VERSION 5.7 ;
  NOWIREEXTENSIONATPIN ON ;
  DIVIDERCHAR "/" ;
  BUSBITCHARS "[]" ;
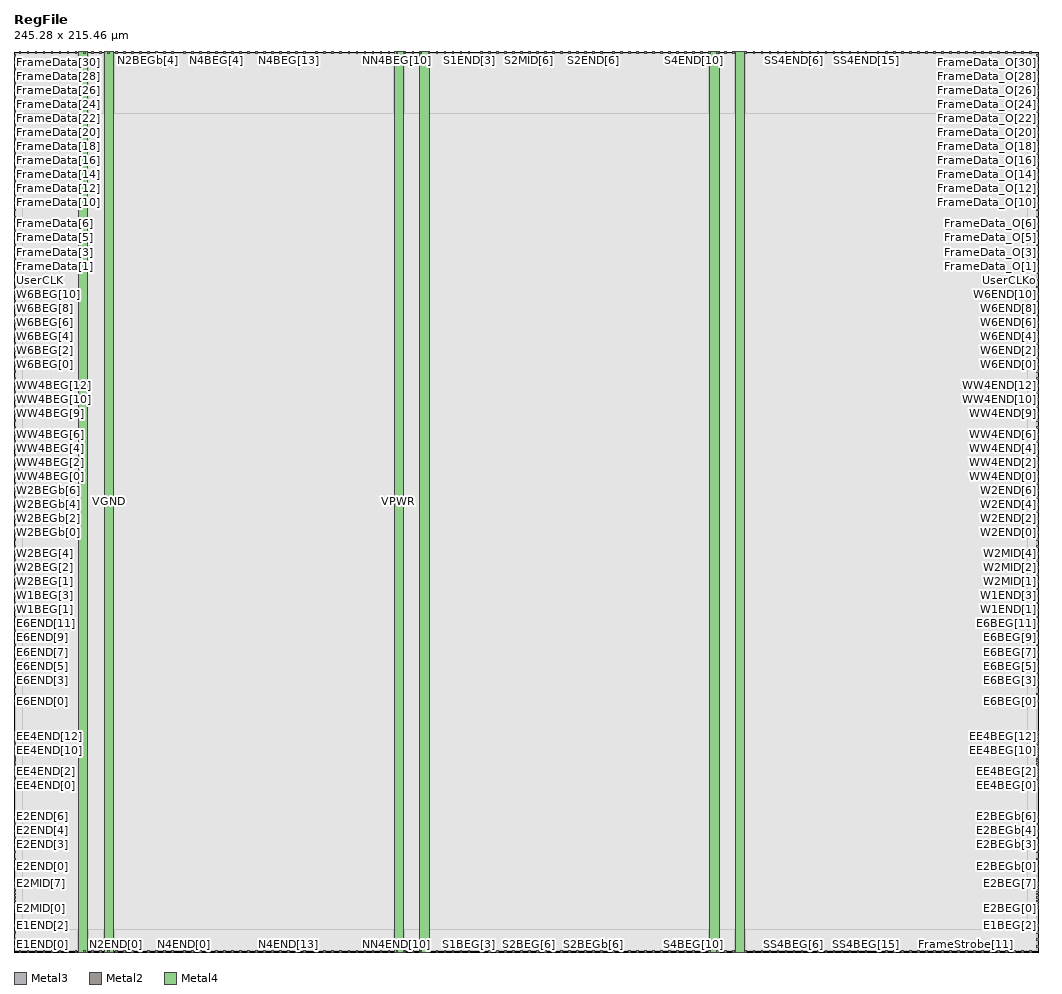
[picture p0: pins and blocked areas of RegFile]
MACRO RegFile
  CLASS BLOCK ;
  FOREIGN RegFile ;
  ORIGIN 0.000 0.000 ;
  SIZE 245.280 BY 215.460 ;
  PIN E1BEG[0]
    DIRECTION OUTPUT ;
    USE SIGNAL ;
    ANTENNADIFFAREA 2.724000 ;
    PORT
      LAYER Metal3 ;
        RECT 244.880 1.060 245.280 1.460 ;
    END
  END E1BEG[0]
  PIN E1BEG[1]
    DIRECTION OUTPUT ;
    USE SIGNAL ;
    ANTENNADIFFAREA 2.724000 ;
    PORT
      LAYER Metal3 ;
        RECT 244.880 2.740 245.280 3.140 ;
    END
  END E1BEG[1]
  PIN E1BEG[2]
    DIRECTION OUTPUT ;
    USE SIGNAL ;
    ANTENNADIFFAREA 2.724000 ;
    PORT
      LAYER Metal3 ;
        RECT 244.880 4.420 245.280 4.820 ;
    END
  END E1BEG[2]
  PIN E1BEG[3]
    DIRECTION OUTPUT ;
    USE SIGNAL ;
    ANTENNADIFFAREA 2.724000 ;
    PORT
      LAYER Metal3 ;
        RECT 244.880 6.100 245.280 6.500 ;
    END
  END E1BEG[3]
  PIN E1END[0]
    DIRECTION INPUT ;
    USE SIGNAL ;
    ANTENNAGATEAREA 1.107600 ;
    PORT
      LAYER Metal3 ;
        RECT 0.000 1.060 0.400 1.460 ;
    END
  END E1END[0]
  PIN E1END[1]
    DIRECTION INPUT ;
    USE SIGNAL ;
    ANTENNAGATEAREA 1.957800 ;
    PORT
      LAYER Metal3 ;
        RECT 0.000 2.740 0.400 3.140 ;
    END
  END E1END[1]
  PIN E1END[2]
    DIRECTION INPUT ;
    USE SIGNAL ;
    ANTENNAGATEAREA 2.319200 ;
    PORT
      LAYER Metal3 ;
        RECT 0.000 4.420 0.400 4.820 ;
    END
  END E1END[2]
  PIN E1END[3]
    DIRECTION INPUT ;
    USE SIGNAL ;
    ANTENNAGATEAREA 2.425800 ;
    PORT
      LAYER Metal3 ;
        RECT 0.000 6.100 0.400 6.500 ;
    END
  END E1END[3]
  PIN E2BEG[0]
    DIRECTION OUTPUT ;
    USE SIGNAL ;
    ANTENNADIFFAREA 2.724000 ;
    PORT
      LAYER Metal3 ;
        RECT 244.880 10.300 245.280 10.700 ;
    END
  END E2BEG[0]
  PIN E2BEG[1]
    DIRECTION OUTPUT ;
    USE SIGNAL ;
    ANTENNADIFFAREA 2.724000 ;
    PORT
      LAYER Metal3 ;
        RECT 244.880 11.140 245.280 11.540 ;
    END
  END E2BEG[1]
  PIN E2BEG[2]
    DIRECTION OUTPUT ;
    USE SIGNAL ;
    ANTENNADIFFAREA 2.724000 ;
    PORT
      LAYER Metal3 ;
        RECT 244.880 11.980 245.280 12.380 ;
    END
  END E2BEG[2]
  PIN E2BEG[3]
    DIRECTION OUTPUT ;
    USE SIGNAL ;
    ANTENNADIFFAREA 2.724000 ;
    PORT
      LAYER Metal3 ;
        RECT 244.880 12.820 245.280 13.220 ;
    END
  END E2BEG[3]
  PIN E2BEG[4]
    DIRECTION OUTPUT ;
    USE SIGNAL ;
    ANTENNADIFFAREA 2.724000 ;
    PORT
      LAYER Metal3 ;
        RECT 244.880 13.660 245.280 14.060 ;
    END
  END E2BEG[4]
  PIN E2BEG[5]
    DIRECTION OUTPUT ;
    USE SIGNAL ;
    ANTENNADIFFAREA 2.724000 ;
    PORT
      LAYER Metal3 ;
        RECT 244.880 14.500 245.280 14.900 ;
    END
  END E2BEG[5]
  PIN E2BEG[6]
    DIRECTION OUTPUT ;
    USE SIGNAL ;
    ANTENNADIFFAREA 2.724000 ;
    PORT
      LAYER Metal3 ;
        RECT 244.880 15.340 245.280 15.740 ;
    END
  END E2BEG[6]
  PIN E2BEG[7]
    DIRECTION OUTPUT ;
    USE SIGNAL ;
    ANTENNADIFFAREA 2.724000 ;
    PORT
      LAYER Metal3 ;
        RECT 244.880 16.180 245.280 16.580 ;
    END
  END E2BEG[7]
  PIN E2BEGb[0]
    DIRECTION OUTPUT ;
    USE SIGNAL ;
    ANTENNADIFFAREA 2.724000 ;
    PORT
      LAYER Metal3 ;
        RECT 244.880 20.380 245.280 20.780 ;
    END
  END E2BEGb[0]
  PIN E2BEGb[1]
    DIRECTION OUTPUT ;
    USE SIGNAL ;
    ANTENNADIFFAREA 2.724000 ;
    PORT
      LAYER Metal3 ;
        RECT 244.880 22.060 245.280 22.460 ;
    END
  END E2BEGb[1]
  PIN E2BEGb[2]
    DIRECTION OUTPUT ;
    USE SIGNAL ;
    ANTENNADIFFAREA 2.724000 ;
    PORT
      LAYER Metal3 ;
        RECT 244.880 23.740 245.280 24.140 ;
    END
  END E2BEGb[2]
  PIN E2BEGb[3]
    DIRECTION OUTPUT ;
    USE SIGNAL ;
    ANTENNADIFFAREA 2.724000 ;
    PORT
      LAYER Metal3 ;
        RECT 244.880 25.420 245.280 25.820 ;
    END
  END E2BEGb[3]
  PIN E2BEGb[4]
    DIRECTION OUTPUT ;
    USE SIGNAL ;
    ANTENNADIFFAREA 2.724000 ;
    PORT
      LAYER Metal3 ;
        RECT 244.880 27.100 245.280 27.500 ;
    END
  END E2BEGb[4]
  PIN E2BEGb[5]
    DIRECTION OUTPUT ;
    USE SIGNAL ;
    ANTENNADIFFAREA 2.724000 ;
    PORT
      LAYER Metal3 ;
        RECT 244.880 28.780 245.280 29.180 ;
    END
  END E2BEGb[5]
  PIN E2BEGb[6]
    DIRECTION OUTPUT ;
    USE SIGNAL ;
    ANTENNADIFFAREA 2.724000 ;
    PORT
      LAYER Metal3 ;
        RECT 244.880 30.460 245.280 30.860 ;
    END
  END E2BEGb[6]
  PIN E2BEGb[7]
    DIRECTION OUTPUT ;
    USE SIGNAL ;
    ANTENNADIFFAREA 2.724000 ;
    PORT
      LAYER Metal3 ;
        RECT 244.880 32.140 245.280 32.540 ;
    END
  END E2BEGb[7]
  PIN E2END[0]
    DIRECTION INPUT ;
    USE SIGNAL ;
    ANTENNAGATEAREA 1.127900 ;
    PORT
      LAYER Metal3 ;
        RECT 0.000 20.380 0.400 20.780 ;
    END
  END E2END[0]
  PIN E2END[1]
    DIRECTION INPUT ;
    USE SIGNAL ;
    ANTENNAGATEAREA 1.029600 ;
    PORT
      LAYER Metal3 ;
        RECT 0.000 22.060 0.400 22.460 ;
    END
  END E2END[1]
  PIN E2END[2]
    DIRECTION INPUT ;
    USE SIGNAL ;
    ANTENNAGATEAREA 1.841600 ;
    PORT
      LAYER Metal3 ;
        RECT 0.000 23.740 0.400 24.140 ;
    END
  END E2END[2]
  PIN E2END[3]
    DIRECTION INPUT ;
    USE SIGNAL ;
    ANTENNAGATEAREA 1.920400 ;
    PORT
      LAYER Metal3 ;
        RECT 0.000 25.420 0.400 25.820 ;
    END
  END E2END[3]
  PIN E2END[4]
    DIRECTION INPUT ;
    USE SIGNAL ;
    ANTENNAGATEAREA 1.092000 ;
    PORT
      LAYER Metal3 ;
        RECT 0.000 27.100 0.400 27.500 ;
    END
  END E2END[4]
  PIN E2END[5]
    DIRECTION INPUT ;
    USE SIGNAL ;
    ANTENNAGATEAREA 1.305200 ;
    PORT
      LAYER Metal3 ;
        RECT 0.000 28.780 0.400 29.180 ;
    END
  END E2END[5]
  PIN E2END[6]
    DIRECTION INPUT ;
    USE SIGNAL ;
    ANTENNAGATEAREA 1.288300 ;
    PORT
      LAYER Metal3 ;
        RECT 0.000 30.460 0.400 30.860 ;
    END
  END E2END[6]
  PIN E2END[7]
    DIRECTION INPUT ;
    USE SIGNAL ;
    ANTENNAGATEAREA 1.120600 ;
    PORT
      LAYER Metal3 ;
        RECT 0.000 32.140 0.400 32.540 ;
    END
  END E2END[7]
  PIN E2MID[0]
    DIRECTION INPUT ;
    USE SIGNAL ;
    ANTENNAGATEAREA 0.635700 ;
    ANTENNADIFFAREA 12.092400 ;
    PORT
      LAYER Metal3 ;
        RECT 0.000 10.300 0.400 10.700 ;
    END
  END E2MID[0]
  PIN E2MID[1]
    DIRECTION INPUT ;
    USE SIGNAL ;
    ANTENNAGATEAREA 1.062100 ;
    PORT
      LAYER Metal3 ;
        RECT 0.000 11.140 0.400 11.540 ;
    END
  END E2MID[1]
  PIN E2MID[2]
    DIRECTION INPUT ;
    USE SIGNAL ;
    ANTENNAGATEAREA 0.820300 ;
    PORT
      LAYER Metal3 ;
        RECT 0.000 11.980 0.400 12.380 ;
    END
  END E2MID[2]
  PIN E2MID[3]
    DIRECTION INPUT ;
    USE SIGNAL ;
    ANTENNAGATEAREA 1.033500 ;
    PORT
      LAYER Metal3 ;
        RECT 0.000 12.820 0.400 13.220 ;
    END
  END E2MID[3]
  PIN E2MID[4]
    DIRECTION INPUT ;
    USE SIGNAL ;
    ANTENNAGATEAREA 0.833300 ;
    PORT
      LAYER Metal3 ;
        RECT 0.000 13.660 0.400 14.060 ;
    END
  END E2MID[4]
  PIN E2MID[5]
    DIRECTION INPUT ;
    USE SIGNAL ;
    ANTENNAGATEAREA 1.046500 ;
    PORT
      LAYER Metal3 ;
        RECT 0.000 14.500 0.400 14.900 ;
    END
  END E2MID[5]
  PIN E2MID[6]
    DIRECTION INPUT ;
    USE SIGNAL ;
    ANTENNAGATEAREA 0.820300 ;
    ANTENNADIFFAREA 8.061600 ;
    PORT
      LAYER Metal3 ;
        RECT 0.000 15.340 0.400 15.740 ;
    END
  END E2MID[6]
  PIN E2MID[7]
    DIRECTION INPUT ;
    USE SIGNAL ;
    ANTENNAGATEAREA 1.046500 ;
    PORT
      LAYER Metal3 ;
        RECT 0.000 16.180 0.400 16.580 ;
    END
  END E2MID[7]
  PIN E6BEG[0]
    DIRECTION OUTPUT ;
    USE SIGNAL ;
    ANTENNADIFFAREA 2.724000 ;
    PORT
      LAYER Metal3 ;
        RECT 244.880 59.860 245.280 60.260 ;
    END
  END E6BEG[0]
  PIN E6BEG[10]
    DIRECTION OUTPUT ;
    USE SIGNAL ;
    ANTENNADIFFAREA 2.724000 ;
    PORT
      LAYER Metal3 ;
        RECT 244.880 76.660 245.280 77.060 ;
    END
  END E6BEG[10]
  PIN E6BEG[11]
    DIRECTION OUTPUT ;
    USE SIGNAL ;
    ANTENNADIFFAREA 2.724000 ;
    PORT
      LAYER Metal3 ;
        RECT 244.880 78.340 245.280 78.740 ;
    END
  END E6BEG[11]
  PIN E6BEG[1]
    DIRECTION OUTPUT ;
    USE SIGNAL ;
    ANTENNADIFFAREA 2.724000 ;
    PORT
      LAYER Metal3 ;
        RECT 244.880 61.540 245.280 61.940 ;
    END
  END E6BEG[1]
  PIN E6BEG[2]
    DIRECTION OUTPUT ;
    USE SIGNAL ;
    ANTENNADIFFAREA 2.724000 ;
    PORT
      LAYER Metal3 ;
        RECT 244.880 63.220 245.280 63.620 ;
    END
  END E6BEG[2]
  PIN E6BEG[3]
    DIRECTION OUTPUT ;
    USE SIGNAL ;
    ANTENNADIFFAREA 2.724000 ;
    PORT
      LAYER Metal3 ;
        RECT 244.880 64.900 245.280 65.300 ;
    END
  END E6BEG[3]
  PIN E6BEG[4]
    DIRECTION OUTPUT ;
    USE SIGNAL ;
    ANTENNADIFFAREA 2.724000 ;
    PORT
      LAYER Metal3 ;
        RECT 244.880 66.580 245.280 66.980 ;
    END
  END E6BEG[4]
  PIN E6BEG[5]
    DIRECTION OUTPUT ;
    USE SIGNAL ;
    ANTENNADIFFAREA 2.724000 ;
    PORT
      LAYER Metal3 ;
        RECT 244.880 68.260 245.280 68.660 ;
    END
  END E6BEG[5]
  PIN E6BEG[6]
    DIRECTION OUTPUT ;
    USE SIGNAL ;
    ANTENNADIFFAREA 2.724000 ;
    PORT
      LAYER Metal3 ;
        RECT 244.880 69.940 245.280 70.340 ;
    END
  END E6BEG[6]
  PIN E6BEG[7]
    DIRECTION OUTPUT ;
    USE SIGNAL ;
    ANTENNADIFFAREA 2.724000 ;
    PORT
      LAYER Metal3 ;
        RECT 244.880 71.620 245.280 72.020 ;
    END
  END E6BEG[7]
  PIN E6BEG[8]
    DIRECTION OUTPUT ;
    USE SIGNAL ;
    ANTENNADIFFAREA 2.724000 ;
    PORT
      LAYER Metal3 ;
        RECT 244.880 73.300 245.280 73.700 ;
    END
  END E6BEG[8]
  PIN E6BEG[9]
    DIRECTION OUTPUT ;
    USE SIGNAL ;
    ANTENNADIFFAREA 2.724000 ;
    PORT
      LAYER Metal3 ;
        RECT 244.880 74.980 245.280 75.380 ;
    END
  END E6BEG[9]
  PIN E6END[0]
    DIRECTION INPUT ;
    USE SIGNAL ;
    ANTENNAGATEAREA 2.633300 ;
    PORT
      LAYER Metal3 ;
        RECT 0.000 59.860 0.400 60.260 ;
    END
  END E6END[0]
  PIN E6END[10]
    DIRECTION INPUT ;
    USE SIGNAL ;
    ANTENNAGATEAREA 0.180700 ;
    PORT
      LAYER Metal3 ;
        RECT 0.000 76.660 0.400 77.060 ;
    END
  END E6END[10]
  PIN E6END[11]
    DIRECTION INPUT ;
    USE SIGNAL ;
    ANTENNAGATEAREA 0.180700 ;
    PORT
      LAYER Metal3 ;
        RECT 0.000 78.340 0.400 78.740 ;
    END
  END E6END[11]
  PIN E6END[1]
    DIRECTION INPUT ;
    USE SIGNAL ;
    ANTENNAGATEAREA 2.641600 ;
    PORT
      LAYER Metal3 ;
        RECT 0.000 61.540 0.400 61.940 ;
    END
  END E6END[1]
  PIN E6END[2]
    DIRECTION INPUT ;
    USE SIGNAL ;
    ANTENNAGATEAREA 0.180700 ;
    PORT
      LAYER Metal3 ;
        RECT 0.000 63.220 0.400 63.620 ;
    END
  END E6END[2]
  PIN E6END[3]
    DIRECTION INPUT ;
    USE SIGNAL ;
    ANTENNAGATEAREA 0.180700 ;
    PORT
      LAYER Metal3 ;
        RECT 0.000 64.900 0.400 65.300 ;
    END
  END E6END[3]
  PIN E6END[4]
    DIRECTION INPUT ;
    USE SIGNAL ;
    ANTENNAGATEAREA 0.180700 ;
    PORT
      LAYER Metal3 ;
        RECT 0.000 66.580 0.400 66.980 ;
    END
  END E6END[4]
  PIN E6END[5]
    DIRECTION INPUT ;
    USE SIGNAL ;
    ANTENNAGATEAREA 0.180700 ;
    PORT
      LAYER Metal3 ;
        RECT 0.000 68.260 0.400 68.660 ;
    END
  END E6END[5]
  PIN E6END[6]
    DIRECTION INPUT ;
    USE SIGNAL ;
    ANTENNAGATEAREA 0.180700 ;
    PORT
      LAYER Metal3 ;
        RECT 0.000 69.940 0.400 70.340 ;
    END
  END E6END[6]
  PIN E6END[7]
    DIRECTION INPUT ;
    USE SIGNAL ;
    ANTENNAGATEAREA 0.180700 ;
    PORT
      LAYER Metal3 ;
        RECT 0.000 71.620 0.400 72.020 ;
    END
  END E6END[7]
  PIN E6END[8]
    DIRECTION INPUT ;
    USE SIGNAL ;
    ANTENNAGATEAREA 0.180700 ;
    PORT
      LAYER Metal3 ;
        RECT 0.000 73.300 0.400 73.700 ;
    END
  END E6END[8]
  PIN E6END[9]
    DIRECTION INPUT ;
    USE SIGNAL ;
    ANTENNAGATEAREA 0.180700 ;
    PORT
      LAYER Metal3 ;
        RECT 0.000 74.980 0.400 75.380 ;
    END
  END E6END[9]
  PIN EE4BEG[0]
    DIRECTION OUTPUT ;
    USE SIGNAL ;
    ANTENNADIFFAREA 2.724000 ;
    PORT
      LAYER Metal3 ;
        RECT 244.880 39.700 245.280 40.100 ;
    END
  END EE4BEG[0]
  PIN EE4BEG[10]
    DIRECTION OUTPUT ;
    USE SIGNAL ;
    ANTENNADIFFAREA 2.724000 ;
    PORT
      LAYER Metal3 ;
        RECT 244.880 48.100 245.280 48.500 ;
    END
  END EE4BEG[10]
  PIN EE4BEG[11]
    DIRECTION OUTPUT ;
    USE SIGNAL ;
    ANTENNADIFFAREA 2.724000 ;
    PORT
      LAYER Metal3 ;
        RECT 244.880 48.940 245.280 49.340 ;
    END
  END EE4BEG[11]
  PIN EE4BEG[12]
    DIRECTION OUTPUT ;
    USE SIGNAL ;
    ANTENNADIFFAREA 2.724000 ;
    PORT
      LAYER Metal3 ;
        RECT 244.880 49.780 245.280 50.180 ;
    END
  END EE4BEG[12]
  PIN EE4BEG[13]
    DIRECTION OUTPUT ;
    USE SIGNAL ;
    ANTENNADIFFAREA 2.724000 ;
    PORT
      LAYER Metal3 ;
        RECT 244.880 50.620 245.280 51.020 ;
    END
  END EE4BEG[13]
  PIN EE4BEG[14]
    DIRECTION OUTPUT ;
    USE SIGNAL ;
    ANTENNADIFFAREA 2.724000 ;
    PORT
      LAYER Metal3 ;
        RECT 244.880 51.460 245.280 51.860 ;
    END
  END EE4BEG[14]
  PIN EE4BEG[15]
    DIRECTION OUTPUT ;
    USE SIGNAL ;
    ANTENNADIFFAREA 2.724000 ;
    PORT
      LAYER Metal3 ;
        RECT 244.880 52.300 245.280 52.700 ;
    END
  END EE4BEG[15]
  PIN EE4BEG[1]
    DIRECTION OUTPUT ;
    USE SIGNAL ;
    ANTENNADIFFAREA 2.724000 ;
    PORT
      LAYER Metal3 ;
        RECT 244.880 40.540 245.280 40.940 ;
    END
  END EE4BEG[1]
  PIN EE4BEG[2]
    DIRECTION OUTPUT ;
    USE SIGNAL ;
    ANTENNADIFFAREA 2.724000 ;
    PORT
      LAYER Metal3 ;
        RECT 244.880 41.380 245.280 41.780 ;
    END
  END EE4BEG[2]
  PIN EE4BEG[3]
    DIRECTION OUTPUT ;
    USE SIGNAL ;
    ANTENNADIFFAREA 2.724000 ;
    PORT
      LAYER Metal3 ;
        RECT 244.880 42.220 245.280 42.620 ;
    END
  END EE4BEG[3]
  PIN EE4BEG[4]
    DIRECTION OUTPUT ;
    USE SIGNAL ;
    ANTENNADIFFAREA 2.724000 ;
    PORT
      LAYER Metal3 ;
        RECT 244.880 43.060 245.280 43.460 ;
    END
  END EE4BEG[4]
  PIN EE4BEG[5]
    DIRECTION OUTPUT ;
    USE SIGNAL ;
    ANTENNADIFFAREA 2.724000 ;
    PORT
      LAYER Metal3 ;
        RECT 244.880 43.900 245.280 44.300 ;
    END
  END EE4BEG[5]
  PIN EE4BEG[6]
    DIRECTION OUTPUT ;
    USE SIGNAL ;
    ANTENNADIFFAREA 2.724000 ;
    PORT
      LAYER Metal3 ;
        RECT 244.880 44.740 245.280 45.140 ;
    END
  END EE4BEG[6]
  PIN EE4BEG[7]
    DIRECTION OUTPUT ;
    USE SIGNAL ;
    ANTENNADIFFAREA 2.724000 ;
    PORT
      LAYER Metal3 ;
        RECT 244.880 45.580 245.280 45.980 ;
    END
  END EE4BEG[7]
  PIN EE4BEG[8]
    DIRECTION OUTPUT ;
    USE SIGNAL ;
    ANTENNADIFFAREA 2.724000 ;
    PORT
      LAYER Metal3 ;
        RECT 244.880 46.420 245.280 46.820 ;
    END
  END EE4BEG[8]
  PIN EE4BEG[9]
    DIRECTION OUTPUT ;
    USE SIGNAL ;
    ANTENNADIFFAREA 2.724000 ;
    PORT
      LAYER Metal3 ;
        RECT 244.880 47.260 245.280 47.660 ;
    END
  END EE4BEG[9]
  PIN EE4END[0]
    DIRECTION INPUT ;
    USE SIGNAL ;
    ANTENNAGATEAREA 0.894400 ;
    PORT
      LAYER Metal3 ;
        RECT 0.000 39.700 0.400 40.100 ;
    END
  END EE4END[0]
  PIN EE4END[10]
    DIRECTION INPUT ;
    USE SIGNAL ;
    ANTENNAGATEAREA 0.180700 ;
    PORT
      LAYER Metal3 ;
        RECT 0.000 48.100 0.400 48.500 ;
    END
  END EE4END[10]
  PIN EE4END[11]
    DIRECTION INPUT ;
    USE SIGNAL ;
    ANTENNAGATEAREA 0.180700 ;
    PORT
      LAYER Metal3 ;
        RECT 0.000 48.940 0.400 49.340 ;
    END
  END EE4END[11]
  PIN EE4END[12]
    DIRECTION INPUT ;
    USE SIGNAL ;
    ANTENNAGATEAREA 0.180700 ;
    PORT
      LAYER Metal3 ;
        RECT 0.000 49.780 0.400 50.180 ;
    END
  END EE4END[12]
  PIN EE4END[13]
    DIRECTION INPUT ;
    USE SIGNAL ;
    ANTENNAGATEAREA 0.180700 ;
    PORT
      LAYER Metal3 ;
        RECT 0.000 50.620 0.400 51.020 ;
    END
  END EE4END[13]
  PIN EE4END[14]
    DIRECTION INPUT ;
    USE SIGNAL ;
    ANTENNAGATEAREA 0.180700 ;
    PORT
      LAYER Metal3 ;
        RECT 0.000 51.460 0.400 51.860 ;
    END
  END EE4END[14]
  PIN EE4END[15]
    DIRECTION INPUT ;
    USE SIGNAL ;
    ANTENNAGATEAREA 0.180700 ;
    PORT
      LAYER Metal3 ;
        RECT 0.000 52.300 0.400 52.700 ;
    END
  END EE4END[15]
  PIN EE4END[1]
    DIRECTION INPUT ;
    USE SIGNAL ;
    ANTENNAGATEAREA 0.878800 ;
    PORT
      LAYER Metal3 ;
        RECT 0.000 40.540 0.400 40.940 ;
    END
  END EE4END[1]
  PIN EE4END[2]
    DIRECTION INPUT ;
    USE SIGNAL ;
    ANTENNAGATEAREA 0.865800 ;
    PORT
      LAYER Metal3 ;
        RECT 0.000 41.380 0.400 41.780 ;
    END
  END EE4END[2]
  PIN EE4END[3]
    DIRECTION INPUT ;
    USE SIGNAL ;
    ANTENNAGATEAREA 0.918600 ;
    PORT
      LAYER Metal3 ;
        RECT 0.000 42.220 0.400 42.620 ;
    END
  END EE4END[3]
  PIN EE4END[4]
    DIRECTION INPUT ;
    USE SIGNAL ;
    ANTENNAGATEAREA 0.180700 ;
    PORT
      LAYER Metal3 ;
        RECT 0.000 43.060 0.400 43.460 ;
    END
  END EE4END[4]
  PIN EE4END[5]
    DIRECTION INPUT ;
    USE SIGNAL ;
    ANTENNAGATEAREA 0.180700 ;
    PORT
      LAYER Metal3 ;
        RECT 0.000 43.900 0.400 44.300 ;
    END
  END EE4END[5]
  PIN EE4END[6]
    DIRECTION INPUT ;
    USE SIGNAL ;
    ANTENNAGATEAREA 0.180700 ;
    PORT
      LAYER Metal3 ;
        RECT 0.000 44.740 0.400 45.140 ;
    END
  END EE4END[6]
  PIN EE4END[7]
    DIRECTION INPUT ;
    USE SIGNAL ;
    ANTENNAGATEAREA 0.180700 ;
    PORT
      LAYER Metal3 ;
        RECT 0.000 45.580 0.400 45.980 ;
    END
  END EE4END[7]
  PIN EE4END[8]
    DIRECTION INPUT ;
    USE SIGNAL ;
    ANTENNAGATEAREA 0.180700 ;
    PORT
      LAYER Metal3 ;
        RECT 0.000 46.420 0.400 46.820 ;
    END
  END EE4END[8]
  PIN EE4END[9]
    DIRECTION INPUT ;
    USE SIGNAL ;
    ANTENNAGATEAREA 0.180700 ;
    PORT
      LAYER Metal3 ;
        RECT 0.000 47.260 0.400 47.660 ;
    END
  END EE4END[9]
  PIN FrameData[0]
    DIRECTION INPUT ;
    USE SIGNAL ;
    ANTENNAGATEAREA 2.349100 ;
    PORT
      LAYER Metal3 ;
        RECT 0.000 162.340 0.400 162.740 ;
    END
  END FrameData[0]
  PIN FrameData[10]
    DIRECTION INPUT ;
    USE SIGNAL ;
    ANTENNAGATEAREA 2.529800 ;
    PORT
      LAYER Metal3 ;
        RECT 0.000 179.140 0.400 179.540 ;
    END
  END FrameData[10]
  PIN FrameData[11]
    DIRECTION INPUT ;
    USE SIGNAL ;
    ANTENNAGATEAREA 2.529800 ;
    PORT
      LAYER Metal3 ;
        RECT 0.000 180.820 0.400 181.220 ;
    END
  END FrameData[11]
  PIN FrameData[12]
    DIRECTION INPUT ;
    USE SIGNAL ;
    ANTENNAGATEAREA 2.529800 ;
    PORT
      LAYER Metal3 ;
        RECT 0.000 182.500 0.400 182.900 ;
    END
  END FrameData[12]
  PIN FrameData[13]
    DIRECTION INPUT ;
    USE SIGNAL ;
    ANTENNAGATEAREA 2.529800 ;
    PORT
      LAYER Metal3 ;
        RECT 0.000 184.180 0.400 184.580 ;
    END
  END FrameData[13]
  PIN FrameData[14]
    DIRECTION INPUT ;
    USE SIGNAL ;
    ANTENNAGATEAREA 2.529800 ;
    PORT
      LAYER Metal3 ;
        RECT 0.000 185.860 0.400 186.260 ;
    END
  END FrameData[14]
  PIN FrameData[15]
    DIRECTION INPUT ;
    USE SIGNAL ;
    ANTENNAGATEAREA 2.529800 ;
    PORT
      LAYER Metal3 ;
        RECT 0.000 187.540 0.400 187.940 ;
    END
  END FrameData[15]
  PIN FrameData[16]
    DIRECTION INPUT ;
    USE SIGNAL ;
    ANTENNAGATEAREA 2.529800 ;
    PORT
      LAYER Metal3 ;
        RECT 0.000 189.220 0.400 189.620 ;
    END
  END FrameData[16]
  PIN FrameData[17]
    DIRECTION INPUT ;
    USE SIGNAL ;
    ANTENNAGATEAREA 2.529800 ;
    PORT
      LAYER Metal3 ;
        RECT 0.000 190.900 0.400 191.300 ;
    END
  END FrameData[17]
  PIN FrameData[18]
    DIRECTION INPUT ;
    USE SIGNAL ;
    ANTENNAGATEAREA 2.529800 ;
    PORT
      LAYER Metal3 ;
        RECT 0.000 192.580 0.400 192.980 ;
    END
  END FrameData[18]
  PIN FrameData[19]
    DIRECTION INPUT ;
    USE SIGNAL ;
    ANTENNAGATEAREA 2.529800 ;
    PORT
      LAYER Metal3 ;
        RECT 0.000 194.260 0.400 194.660 ;
    END
  END FrameData[19]
  PIN FrameData[1]
    DIRECTION INPUT ;
    USE SIGNAL ;
    ANTENNAGATEAREA 2.349100 ;
    PORT
      LAYER Metal3 ;
        RECT 0.000 164.020 0.400 164.420 ;
    END
  END FrameData[1]
  PIN FrameData[20]
    DIRECTION INPUT ;
    USE SIGNAL ;
    ANTENNAGATEAREA 2.529800 ;
    PORT
      LAYER Metal3 ;
        RECT 0.000 195.940 0.400 196.340 ;
    END
  END FrameData[20]
  PIN FrameData[21]
    DIRECTION INPUT ;
    USE SIGNAL ;
    ANTENNAGATEAREA 2.529800 ;
    PORT
      LAYER Metal3 ;
        RECT 0.000 197.620 0.400 198.020 ;
    END
  END FrameData[21]
  PIN FrameData[22]
    DIRECTION INPUT ;
    USE SIGNAL ;
    ANTENNAGATEAREA 2.529800 ;
    PORT
      LAYER Metal3 ;
        RECT 0.000 199.300 0.400 199.700 ;
    END
  END FrameData[22]
  PIN FrameData[23]
    DIRECTION INPUT ;
    USE SIGNAL ;
    ANTENNAGATEAREA 2.529800 ;
    PORT
      LAYER Metal3 ;
        RECT 0.000 200.980 0.400 201.380 ;
    END
  END FrameData[23]
  PIN FrameData[24]
    DIRECTION INPUT ;
    USE SIGNAL ;
    ANTENNAGATEAREA 2.529800 ;
    PORT
      LAYER Metal3 ;
        RECT 0.000 202.660 0.400 203.060 ;
    END
  END FrameData[24]
  PIN FrameData[25]
    DIRECTION INPUT ;
    USE SIGNAL ;
    ANTENNAGATEAREA 2.529800 ;
    PORT
      LAYER Metal3 ;
        RECT 0.000 204.340 0.400 204.740 ;
    END
  END FrameData[25]
  PIN FrameData[26]
    DIRECTION INPUT ;
    USE SIGNAL ;
    ANTENNAGATEAREA 2.529800 ;
    PORT
      LAYER Metal3 ;
        RECT 0.000 206.020 0.400 206.420 ;
    END
  END FrameData[26]
  PIN FrameData[27]
    DIRECTION INPUT ;
    USE SIGNAL ;
    ANTENNAGATEAREA 2.529800 ;
    PORT
      LAYER Metal3 ;
        RECT 0.000 207.700 0.400 208.100 ;
    END
  END FrameData[27]
  PIN FrameData[28]
    DIRECTION INPUT ;
    USE SIGNAL ;
    ANTENNAGATEAREA 2.529800 ;
    PORT
      LAYER Metal3 ;
        RECT 0.000 209.380 0.400 209.780 ;
    END
  END FrameData[28]
  PIN FrameData[29]
    DIRECTION INPUT ;
    USE SIGNAL ;
    ANTENNAGATEAREA 2.529800 ;
    PORT
      LAYER Metal3 ;
        RECT 0.000 211.060 0.400 211.460 ;
    END
  END FrameData[29]
  PIN FrameData[2]
    DIRECTION INPUT ;
    USE SIGNAL ;
    ANTENNAGATEAREA 2.529800 ;
    PORT
      LAYER Metal3 ;
        RECT 0.000 165.700 0.400 166.100 ;
    END
  END FrameData[2]
  PIN FrameData[30]
    DIRECTION INPUT ;
    USE SIGNAL ;
    ANTENNAGATEAREA 2.529800 ;
    ANTENNADIFFAREA 28.215599 ;
    PORT
      LAYER Metal3 ;
        RECT 0.000 212.740 0.400 213.140 ;
    END
  END FrameData[30]
  PIN FrameData[31]
    DIRECTION INPUT ;
    USE SIGNAL ;
    ANTENNAGATEAREA 2.529800 ;
    PORT
      LAYER Metal3 ;
        RECT 0.000 214.420 0.400 214.820 ;
    END
  END FrameData[31]
  PIN FrameData[3]
    DIRECTION INPUT ;
    USE SIGNAL ;
    ANTENNAGATEAREA 2.529800 ;
    ANTENNADIFFAREA 64.492798 ;
    PORT
      LAYER Metal3 ;
        RECT 0.000 167.380 0.400 167.780 ;
    END
  END FrameData[3]
  PIN FrameData[4]
    DIRECTION INPUT ;
    USE SIGNAL ;
    ANTENNAGATEAREA 2.529800 ;
    PORT
      LAYER Metal3 ;
        RECT 0.000 169.060 0.400 169.460 ;
    END
  END FrameData[4]
  PIN FrameData[5]
    DIRECTION INPUT ;
    USE SIGNAL ;
    ANTENNAGATEAREA 2.529800 ;
    PORT
      LAYER Metal3 ;
        RECT 0.000 170.740 0.400 171.140 ;
    END
  END FrameData[5]
  PIN FrameData[6]
    DIRECTION INPUT ;
    USE SIGNAL ;
    ANTENNAGATEAREA 2.529800 ;
    PORT
      LAYER Metal3 ;
        RECT 0.000 172.420 0.400 172.820 ;
    END
  END FrameData[6]
  PIN FrameData[7]
    DIRECTION INPUT ;
    USE SIGNAL ;
    ANTENNAGATEAREA 2.529800 ;
    PORT
      LAYER Metal3 ;
        RECT 0.000 174.100 0.400 174.500 ;
    END
  END FrameData[7]
  PIN FrameData[8]
    DIRECTION INPUT ;
    USE SIGNAL ;
    ANTENNAGATEAREA 2.529800 ;
    PORT
      LAYER Metal3 ;
        RECT 0.000 175.780 0.400 176.180 ;
    END
  END FrameData[8]
  PIN FrameData[9]
    DIRECTION INPUT ;
    USE SIGNAL ;
    ANTENNAGATEAREA 2.529800 ;
    PORT
      LAYER Metal3 ;
        RECT 0.000 177.460 0.400 177.860 ;
    END
  END FrameData[9]
  PIN FrameData_O[0]
    DIRECTION OUTPUT ;
    USE SIGNAL ;
    ANTENNADIFFAREA 2.724000 ;
    PORT
      LAYER Metal3 ;
        RECT 244.880 162.340 245.280 162.740 ;
    END
  END FrameData_O[0]
  PIN FrameData_O[10]
    DIRECTION OUTPUT ;
    USE SIGNAL ;
    ANTENNADIFFAREA 2.724000 ;
    PORT
      LAYER Metal3 ;
        RECT 244.880 179.140 245.280 179.540 ;
    END
  END FrameData_O[10]
  PIN FrameData_O[11]
    DIRECTION OUTPUT ;
    USE SIGNAL ;
    ANTENNADIFFAREA 2.724000 ;
    PORT
      LAYER Metal3 ;
        RECT 244.880 180.820 245.280 181.220 ;
    END
  END FrameData_O[11]
  PIN FrameData_O[12]
    DIRECTION OUTPUT ;
    USE SIGNAL ;
    ANTENNADIFFAREA 2.724000 ;
    PORT
      LAYER Metal3 ;
        RECT 244.880 182.500 245.280 182.900 ;
    END
  END FrameData_O[12]
  PIN FrameData_O[13]
    DIRECTION OUTPUT ;
    USE SIGNAL ;
    ANTENNADIFFAREA 2.724000 ;
    PORT
      LAYER Metal3 ;
        RECT 244.880 184.180 245.280 184.580 ;
    END
  END FrameData_O[13]
  PIN FrameData_O[14]
    DIRECTION OUTPUT ;
    USE SIGNAL ;
    ANTENNADIFFAREA 2.724000 ;
    PORT
      LAYER Metal3 ;
        RECT 244.880 185.860 245.280 186.260 ;
    END
  END FrameData_O[14]
  PIN FrameData_O[15]
    DIRECTION OUTPUT ;
    USE SIGNAL ;
    ANTENNADIFFAREA 2.724000 ;
    PORT
      LAYER Metal3 ;
        RECT 244.880 187.540 245.280 187.940 ;
    END
  END FrameData_O[15]
  PIN FrameData_O[16]
    DIRECTION OUTPUT ;
    USE SIGNAL ;
    ANTENNADIFFAREA 2.724000 ;
    PORT
      LAYER Metal3 ;
        RECT 244.880 189.220 245.280 189.620 ;
    END
  END FrameData_O[16]
  PIN FrameData_O[17]
    DIRECTION OUTPUT ;
    USE SIGNAL ;
    ANTENNADIFFAREA 2.724000 ;
    PORT
      LAYER Metal3 ;
        RECT 244.880 190.900 245.280 191.300 ;
    END
  END FrameData_O[17]
  PIN FrameData_O[18]
    DIRECTION OUTPUT ;
    USE SIGNAL ;
    ANTENNADIFFAREA 2.724000 ;
    PORT
      LAYER Metal3 ;
        RECT 244.880 192.580 245.280 192.980 ;
    END
  END FrameData_O[18]
  PIN FrameData_O[19]
    DIRECTION OUTPUT ;
    USE SIGNAL ;
    ANTENNADIFFAREA 2.724000 ;
    PORT
      LAYER Metal3 ;
        RECT 244.880 194.260 245.280 194.660 ;
    END
  END FrameData_O[19]
  PIN FrameData_O[1]
    DIRECTION OUTPUT ;
    USE SIGNAL ;
    ANTENNADIFFAREA 2.724000 ;
    PORT
      LAYER Metal3 ;
        RECT 244.880 164.020 245.280 164.420 ;
    END
  END FrameData_O[1]
  PIN FrameData_O[20]
    DIRECTION OUTPUT ;
    USE SIGNAL ;
    ANTENNADIFFAREA 2.724000 ;
    PORT
      LAYER Metal3 ;
        RECT 244.880 195.940 245.280 196.340 ;
    END
  END FrameData_O[20]
  PIN FrameData_O[21]
    DIRECTION OUTPUT ;
    USE SIGNAL ;
    ANTENNADIFFAREA 2.724000 ;
    PORT
      LAYER Metal3 ;
        RECT 244.880 197.620 245.280 198.020 ;
    END
  END FrameData_O[21]
  PIN FrameData_O[22]
    DIRECTION OUTPUT ;
    USE SIGNAL ;
    ANTENNADIFFAREA 2.724000 ;
    PORT
      LAYER Metal3 ;
        RECT 244.880 199.300 245.280 199.700 ;
    END
  END FrameData_O[22]
  PIN FrameData_O[23]
    DIRECTION OUTPUT ;
    USE SIGNAL ;
    ANTENNADIFFAREA 2.724000 ;
    PORT
      LAYER Metal3 ;
        RECT 244.880 200.980 245.280 201.380 ;
    END
  END FrameData_O[23]
  PIN FrameData_O[24]
    DIRECTION OUTPUT ;
    USE SIGNAL ;
    ANTENNADIFFAREA 2.724000 ;
    PORT
      LAYER Metal3 ;
        RECT 244.880 202.660 245.280 203.060 ;
    END
  END FrameData_O[24]
  PIN FrameData_O[25]
    DIRECTION OUTPUT ;
    USE SIGNAL ;
    ANTENNADIFFAREA 2.724000 ;
    PORT
      LAYER Metal3 ;
        RECT 244.880 204.340 245.280 204.740 ;
    END
  END FrameData_O[25]
  PIN FrameData_O[26]
    DIRECTION OUTPUT ;
    USE SIGNAL ;
    ANTENNADIFFAREA 2.724000 ;
    PORT
      LAYER Metal3 ;
        RECT 244.880 206.020 245.280 206.420 ;
    END
  END FrameData_O[26]
  PIN FrameData_O[27]
    DIRECTION OUTPUT ;
    USE SIGNAL ;
    ANTENNADIFFAREA 2.724000 ;
    PORT
      LAYER Metal3 ;
        RECT 244.880 207.700 245.280 208.100 ;
    END
  END FrameData_O[27]
  PIN FrameData_O[28]
    DIRECTION OUTPUT ;
    USE SIGNAL ;
    ANTENNADIFFAREA 2.724000 ;
    PORT
      LAYER Metal3 ;
        RECT 244.880 209.380 245.280 209.780 ;
    END
  END FrameData_O[28]
  PIN FrameData_O[29]
    DIRECTION OUTPUT ;
    USE SIGNAL ;
    ANTENNADIFFAREA 2.724000 ;
    PORT
      LAYER Metal3 ;
        RECT 244.880 211.060 245.280 211.460 ;
    END
  END FrameData_O[29]
  PIN FrameData_O[2]
    DIRECTION OUTPUT ;
    USE SIGNAL ;
    ANTENNADIFFAREA 2.724000 ;
    PORT
      LAYER Metal3 ;
        RECT 244.880 165.700 245.280 166.100 ;
    END
  END FrameData_O[2]
  PIN FrameData_O[30]
    DIRECTION OUTPUT ;
    USE SIGNAL ;
    ANTENNADIFFAREA 2.724000 ;
    PORT
      LAYER Metal3 ;
        RECT 244.880 212.740 245.280 213.140 ;
    END
  END FrameData_O[30]
  PIN FrameData_O[31]
    DIRECTION OUTPUT ;
    USE SIGNAL ;
    ANTENNADIFFAREA 2.724000 ;
    PORT
      LAYER Metal3 ;
        RECT 244.880 214.420 245.280 214.820 ;
    END
  END FrameData_O[31]
  PIN FrameData_O[3]
    DIRECTION OUTPUT ;
    USE SIGNAL ;
    ANTENNADIFFAREA 2.724000 ;
    PORT
      LAYER Metal3 ;
        RECT 244.880 167.380 245.280 167.780 ;
    END
  END FrameData_O[3]
  PIN FrameData_O[4]
    DIRECTION OUTPUT ;
    USE SIGNAL ;
    ANTENNADIFFAREA 2.724000 ;
    PORT
      LAYER Metal3 ;
        RECT 244.880 169.060 245.280 169.460 ;
    END
  END FrameData_O[4]
  PIN FrameData_O[5]
    DIRECTION OUTPUT ;
    USE SIGNAL ;
    ANTENNADIFFAREA 2.724000 ;
    PORT
      LAYER Metal3 ;
        RECT 244.880 170.740 245.280 171.140 ;
    END
  END FrameData_O[5]
  PIN FrameData_O[6]
    DIRECTION OUTPUT ;
    USE SIGNAL ;
    ANTENNADIFFAREA 2.724000 ;
    PORT
      LAYER Metal3 ;
        RECT 244.880 172.420 245.280 172.820 ;
    END
  END FrameData_O[6]
  PIN FrameData_O[7]
    DIRECTION OUTPUT ;
    USE SIGNAL ;
    ANTENNADIFFAREA 2.724000 ;
    PORT
      LAYER Metal3 ;
        RECT 244.880 174.100 245.280 174.500 ;
    END
  END FrameData_O[7]
  PIN FrameData_O[8]
    DIRECTION OUTPUT ;
    USE SIGNAL ;
    ANTENNADIFFAREA 2.724000 ;
    PORT
      LAYER Metal3 ;
        RECT 244.880 175.780 245.280 176.180 ;
    END
  END FrameData_O[8]
  PIN FrameData_O[9]
    DIRECTION OUTPUT ;
    USE SIGNAL ;
    ANTENNADIFFAREA 2.724000 ;
    PORT
      LAYER Metal3 ;
        RECT 244.880 177.460 245.280 177.860 ;
    END
  END FrameData_O[9]
  PIN FrameStrobe[0]
    DIRECTION INPUT ;
    USE SIGNAL ;
    ANTENNAGATEAREA 6.753500 ;
    PORT
      LAYER Metal2 ;
        RECT 206.680 0.000 207.080 0.400 ;
    END
  END FrameStrobe[0]
  PIN FrameStrobe[10]
    DIRECTION INPUT ;
    USE SIGNAL ;
    ANTENNAGATEAREA 6.753500 ;
    PORT
      LAYER Metal2 ;
        RECT 225.880 0.000 226.280 0.400 ;
    END
  END FrameStrobe[10]
  PIN FrameStrobe[11]
    DIRECTION INPUT ;
    USE SIGNAL ;
    ANTENNAGATEAREA 6.753500 ;
    PORT
      LAYER Metal2 ;
        RECT 227.800 0.000 228.200 0.400 ;
    END
  END FrameStrobe[11]
  PIN FrameStrobe[12]
    DIRECTION INPUT ;
    USE SIGNAL ;
    ANTENNAGATEAREA 6.342700 ;
    PORT
      LAYER Metal2 ;
        RECT 229.720 0.000 230.120 0.400 ;
    END
  END FrameStrobe[12]
  PIN FrameStrobe[13]
    DIRECTION INPUT ;
    USE SIGNAL ;
    ANTENNAGATEAREA 0.180700 ;
    PORT
      LAYER Metal2 ;
        RECT 231.640 0.000 232.040 0.400 ;
    END
  END FrameStrobe[13]
  PIN FrameStrobe[14]
    DIRECTION INPUT ;
    USE SIGNAL ;
    ANTENNAGATEAREA 0.180700 ;
    PORT
      LAYER Metal2 ;
        RECT 233.560 0.000 233.960 0.400 ;
    END
  END FrameStrobe[14]
  PIN FrameStrobe[15]
    DIRECTION INPUT ;
    USE SIGNAL ;
    ANTENNAGATEAREA 0.180700 ;
    PORT
      LAYER Metal2 ;
        RECT 235.480 0.000 235.880 0.400 ;
    END
  END FrameStrobe[15]
  PIN FrameStrobe[16]
    DIRECTION INPUT ;
    USE SIGNAL ;
    ANTENNAGATEAREA 0.180700 ;
    PORT
      LAYER Metal2 ;
        RECT 237.400 0.000 237.800 0.400 ;
    END
  END FrameStrobe[16]
  PIN FrameStrobe[17]
    DIRECTION INPUT ;
    USE SIGNAL ;
    ANTENNAGATEAREA 0.180700 ;
    PORT
      LAYER Metal2 ;
        RECT 239.320 0.000 239.720 0.400 ;
    END
  END FrameStrobe[17]
  PIN FrameStrobe[18]
    DIRECTION INPUT ;
    USE SIGNAL ;
    ANTENNAGATEAREA 0.180700 ;
    PORT
      LAYER Metal2 ;
        RECT 241.240 0.000 241.640 0.400 ;
    END
  END FrameStrobe[18]
  PIN FrameStrobe[19]
    DIRECTION INPUT ;
    USE SIGNAL ;
    ANTENNAGATEAREA 0.180700 ;
    PORT
      LAYER Metal2 ;
        RECT 243.160 0.000 243.560 0.400 ;
    END
  END FrameStrobe[19]
  PIN FrameStrobe[1]
    DIRECTION INPUT ;
    USE SIGNAL ;
    ANTENNAGATEAREA 6.753500 ;
    PORT
      LAYER Metal2 ;
        RECT 208.600 0.000 209.000 0.400 ;
    END
  END FrameStrobe[1]
  PIN FrameStrobe[2]
    DIRECTION INPUT ;
    USE SIGNAL ;
    ANTENNAGATEAREA 6.753500 ;
    PORT
      LAYER Metal2 ;
        RECT 210.520 0.000 210.920 0.400 ;
    END
  END FrameStrobe[2]
  PIN FrameStrobe[3]
    DIRECTION INPUT ;
    USE SIGNAL ;
    ANTENNAGATEAREA 6.753500 ;
    PORT
      LAYER Metal2 ;
        RECT 212.440 0.000 212.840 0.400 ;
    END
  END FrameStrobe[3]
  PIN FrameStrobe[4]
    DIRECTION INPUT ;
    USE SIGNAL ;
    ANTENNAGATEAREA 6.753500 ;
    PORT
      LAYER Metal2 ;
        RECT 214.360 0.000 214.760 0.400 ;
    END
  END FrameStrobe[4]
  PIN FrameStrobe[5]
    DIRECTION INPUT ;
    USE SIGNAL ;
    ANTENNAGATEAREA 6.753500 ;
    PORT
      LAYER Metal2 ;
        RECT 216.280 0.000 216.680 0.400 ;
    END
  END FrameStrobe[5]
  PIN FrameStrobe[6]
    DIRECTION INPUT ;
    USE SIGNAL ;
    ANTENNAGATEAREA 6.753500 ;
    PORT
      LAYER Metal2 ;
        RECT 218.200 0.000 218.600 0.400 ;
    END
  END FrameStrobe[6]
  PIN FrameStrobe[7]
    DIRECTION INPUT ;
    USE SIGNAL ;
    ANTENNAGATEAREA 6.753500 ;
    PORT
      LAYER Metal2 ;
        RECT 220.120 0.000 220.520 0.400 ;
    END
  END FrameStrobe[7]
  PIN FrameStrobe[8]
    DIRECTION INPUT ;
    USE SIGNAL ;
    ANTENNAGATEAREA 6.753500 ;
    PORT
      LAYER Metal2 ;
        RECT 222.040 0.000 222.440 0.400 ;
    END
  END FrameStrobe[8]
  PIN FrameStrobe[9]
    DIRECTION INPUT ;
    USE SIGNAL ;
    ANTENNAGATEAREA 6.753500 ;
    PORT
      LAYER Metal2 ;
        RECT 223.960 0.000 224.360 0.400 ;
    END
  END FrameStrobe[9]
  PIN FrameStrobe_O[0]
    DIRECTION OUTPUT ;
    USE SIGNAL ;
    ANTENNADIFFAREA 2.724000 ;
    PORT
      LAYER Metal2 ;
        RECT 206.680 215.060 207.080 215.460 ;
    END
  END FrameStrobe_O[0]
  PIN FrameStrobe_O[10]
    DIRECTION OUTPUT ;
    USE SIGNAL ;
    ANTENNADIFFAREA 2.724000 ;
    PORT
      LAYER Metal2 ;
        RECT 225.880 215.060 226.280 215.460 ;
    END
  END FrameStrobe_O[10]
  PIN FrameStrobe_O[11]
    DIRECTION OUTPUT ;
    USE SIGNAL ;
    ANTENNADIFFAREA 2.724000 ;
    PORT
      LAYER Metal2 ;
        RECT 227.800 215.060 228.200 215.460 ;
    END
  END FrameStrobe_O[11]
  PIN FrameStrobe_O[12]
    DIRECTION OUTPUT ;
    USE SIGNAL ;
    ANTENNADIFFAREA 2.724000 ;
    PORT
      LAYER Metal2 ;
        RECT 229.720 215.060 230.120 215.460 ;
    END
  END FrameStrobe_O[12]
  PIN FrameStrobe_O[13]
    DIRECTION OUTPUT ;
    USE SIGNAL ;
    ANTENNADIFFAREA 2.724000 ;
    PORT
      LAYER Metal2 ;
        RECT 231.640 215.060 232.040 215.460 ;
    END
  END FrameStrobe_O[13]
  PIN FrameStrobe_O[14]
    DIRECTION OUTPUT ;
    USE SIGNAL ;
    ANTENNADIFFAREA 2.724000 ;
    PORT
      LAYER Metal2 ;
        RECT 233.560 215.060 233.960 215.460 ;
    END
  END FrameStrobe_O[14]
  PIN FrameStrobe_O[15]
    DIRECTION OUTPUT ;
    USE SIGNAL ;
    ANTENNADIFFAREA 2.724000 ;
    PORT
      LAYER Metal2 ;
        RECT 235.480 215.060 235.880 215.460 ;
    END
  END FrameStrobe_O[15]
  PIN FrameStrobe_O[16]
    DIRECTION OUTPUT ;
    USE SIGNAL ;
    ANTENNADIFFAREA 2.724000 ;
    PORT
      LAYER Metal2 ;
        RECT 237.400 215.060 237.800 215.460 ;
    END
  END FrameStrobe_O[16]
  PIN FrameStrobe_O[17]
    DIRECTION OUTPUT ;
    USE SIGNAL ;
    ANTENNADIFFAREA 2.724000 ;
    PORT
      LAYER Metal2 ;
        RECT 239.320 215.060 239.720 215.460 ;
    END
  END FrameStrobe_O[17]
  PIN FrameStrobe_O[18]
    DIRECTION OUTPUT ;
    USE SIGNAL ;
    ANTENNADIFFAREA 2.724000 ;
    PORT
      LAYER Metal2 ;
        RECT 241.240 215.060 241.640 215.460 ;
    END
  END FrameStrobe_O[18]
  PIN FrameStrobe_O[19]
    DIRECTION OUTPUT ;
    USE SIGNAL ;
    ANTENNADIFFAREA 2.724000 ;
    PORT
      LAYER Metal2 ;
        RECT 243.160 215.060 243.560 215.460 ;
    END
  END FrameStrobe_O[19]
  PIN FrameStrobe_O[1]
    DIRECTION OUTPUT ;
    USE SIGNAL ;
    ANTENNADIFFAREA 2.724000 ;
    PORT
      LAYER Metal2 ;
        RECT 208.600 215.060 209.000 215.460 ;
    END
  END FrameStrobe_O[1]
  PIN FrameStrobe_O[2]
    DIRECTION OUTPUT ;
    USE SIGNAL ;
    ANTENNADIFFAREA 2.724000 ;
    PORT
      LAYER Metal2 ;
        RECT 210.520 215.060 210.920 215.460 ;
    END
  END FrameStrobe_O[2]
  PIN FrameStrobe_O[3]
    DIRECTION OUTPUT ;
    USE SIGNAL ;
    ANTENNADIFFAREA 2.724000 ;
    PORT
      LAYER Metal2 ;
        RECT 212.440 215.060 212.840 215.460 ;
    END
  END FrameStrobe_O[3]
  PIN FrameStrobe_O[4]
    DIRECTION OUTPUT ;
    USE SIGNAL ;
    ANTENNADIFFAREA 2.724000 ;
    PORT
      LAYER Metal2 ;
        RECT 214.360 215.060 214.760 215.460 ;
    END
  END FrameStrobe_O[4]
  PIN FrameStrobe_O[5]
    DIRECTION OUTPUT ;
    USE SIGNAL ;
    ANTENNADIFFAREA 2.724000 ;
    PORT
      LAYER Metal2 ;
        RECT 216.280 215.060 216.680 215.460 ;
    END
  END FrameStrobe_O[5]
  PIN FrameStrobe_O[6]
    DIRECTION OUTPUT ;
    USE SIGNAL ;
    ANTENNADIFFAREA 2.724000 ;
    PORT
      LAYER Metal2 ;
        RECT 218.200 215.060 218.600 215.460 ;
    END
  END FrameStrobe_O[6]
  PIN FrameStrobe_O[7]
    DIRECTION OUTPUT ;
    USE SIGNAL ;
    ANTENNADIFFAREA 2.724000 ;
    PORT
      LAYER Metal2 ;
        RECT 220.120 215.060 220.520 215.460 ;
    END
  END FrameStrobe_O[7]
  PIN FrameStrobe_O[8]
    DIRECTION OUTPUT ;
    USE SIGNAL ;
    ANTENNADIFFAREA 2.724000 ;
    PORT
      LAYER Metal2 ;
        RECT 222.040 215.060 222.440 215.460 ;
    END
  END FrameStrobe_O[8]
  PIN FrameStrobe_O[9]
    DIRECTION OUTPUT ;
    USE SIGNAL ;
    ANTENNADIFFAREA 2.724000 ;
    PORT
      LAYER Metal2 ;
        RECT 223.960 215.060 224.360 215.460 ;
    END
  END FrameStrobe_O[9]
  PIN N1BEG[0]
    DIRECTION OUTPUT ;
    USE SIGNAL ;
    ANTENNADIFFAREA 2.724000 ;
    PORT
      LAYER Metal2 ;
        RECT 1.240 215.060 1.640 215.460 ;
    END
  END N1BEG[0]
  PIN N1BEG[1]
    DIRECTION OUTPUT ;
    USE SIGNAL ;
    ANTENNADIFFAREA 2.724000 ;
    PORT
      LAYER Metal2 ;
        RECT 3.160 215.060 3.560 215.460 ;
    END
  END N1BEG[1]
  PIN N1BEG[2]
    DIRECTION OUTPUT ;
    USE SIGNAL ;
    ANTENNADIFFAREA 2.724000 ;
    PORT
      LAYER Metal2 ;
        RECT 5.080 215.060 5.480 215.460 ;
    END
  END N1BEG[2]
  PIN N1BEG[3]
    DIRECTION OUTPUT ;
    USE SIGNAL ;
    ANTENNADIFFAREA 2.724000 ;
    PORT
      LAYER Metal2 ;
        RECT 7.000 215.060 7.400 215.460 ;
    END
  END N1BEG[3]
  PIN N1END[0]
    DIRECTION INPUT ;
    USE SIGNAL ;
    ANTENNAGATEAREA 2.197800 ;
    PORT
      LAYER Metal2 ;
        RECT 1.240 0.000 1.640 0.400 ;
    END
  END N1END[0]
  PIN N1END[1]
    DIRECTION INPUT ;
    USE SIGNAL ;
    ANTENNAGATEAREA 2.145000 ;
    PORT
      LAYER Metal2 ;
        RECT 3.160 0.000 3.560 0.400 ;
    END
  END N1END[1]
  PIN N1END[2]
    DIRECTION INPUT ;
    USE SIGNAL ;
    ANTENNAGATEAREA 2.236800 ;
    PORT
      LAYER Metal2 ;
        RECT 5.080 0.000 5.480 0.400 ;
    END
  END N1END[2]
  PIN N1END[3]
    DIRECTION INPUT ;
    USE SIGNAL ;
    ANTENNAGATEAREA 2.243800 ;
    PORT
      LAYER Metal2 ;
        RECT 7.000 0.000 7.400 0.400 ;
    END
  END N1END[3]
  PIN N2BEG[0]
    DIRECTION OUTPUT ;
    USE SIGNAL ;
    ANTENNADIFFAREA 2.724000 ;
    PORT
      LAYER Metal2 ;
        RECT 8.920 215.060 9.320 215.460 ;
    END
  END N2BEG[0]
  PIN N2BEG[1]
    DIRECTION OUTPUT ;
    USE SIGNAL ;
    ANTENNADIFFAREA 2.724000 ;
    PORT
      LAYER Metal2 ;
        RECT 10.840 215.060 11.240 215.460 ;
    END
  END N2BEG[1]
  PIN N2BEG[2]
    DIRECTION OUTPUT ;
    USE SIGNAL ;
    ANTENNADIFFAREA 2.724000 ;
    PORT
      LAYER Metal2 ;
        RECT 12.760 215.060 13.160 215.460 ;
    END
  END N2BEG[2]
  PIN N2BEG[3]
    DIRECTION OUTPUT ;
    USE SIGNAL ;
    ANTENNADIFFAREA 2.724000 ;
    PORT
      LAYER Metal2 ;
        RECT 14.680 215.060 15.080 215.460 ;
    END
  END N2BEG[3]
  PIN N2BEG[4]
    DIRECTION OUTPUT ;
    USE SIGNAL ;
    ANTENNADIFFAREA 2.724000 ;
    PORT
      LAYER Metal2 ;
        RECT 16.600 215.060 17.000 215.460 ;
    END
  END N2BEG[4]
  PIN N2BEG[5]
    DIRECTION OUTPUT ;
    USE SIGNAL ;
    ANTENNADIFFAREA 2.724000 ;
    PORT
      LAYER Metal2 ;
        RECT 18.520 215.060 18.920 215.460 ;
    END
  END N2BEG[5]
  PIN N2BEG[6]
    DIRECTION OUTPUT ;
    USE SIGNAL ;
    ANTENNADIFFAREA 2.724000 ;
    PORT
      LAYER Metal2 ;
        RECT 20.440 215.060 20.840 215.460 ;
    END
  END N2BEG[6]
  PIN N2BEG[7]
    DIRECTION OUTPUT ;
    USE SIGNAL ;
    ANTENNADIFFAREA 2.724000 ;
    PORT
      LAYER Metal2 ;
        RECT 22.360 215.060 22.760 215.460 ;
    END
  END N2BEG[7]
  PIN N2BEGb[0]
    DIRECTION OUTPUT ;
    USE SIGNAL ;
    ANTENNADIFFAREA 2.724000 ;
    PORT
      LAYER Metal2 ;
        RECT 24.280 215.060 24.680 215.460 ;
    END
  END N2BEGb[0]
  PIN N2BEGb[1]
    DIRECTION OUTPUT ;
    USE SIGNAL ;
    ANTENNADIFFAREA 2.724000 ;
    PORT
      LAYER Metal2 ;
        RECT 26.200 215.060 26.600 215.460 ;
    END
  END N2BEGb[1]
  PIN N2BEGb[2]
    DIRECTION OUTPUT ;
    USE SIGNAL ;
    ANTENNADIFFAREA 2.724000 ;
    PORT
      LAYER Metal2 ;
        RECT 28.120 215.060 28.520 215.460 ;
    END
  END N2BEGb[2]
  PIN N2BEGb[3]
    DIRECTION OUTPUT ;
    USE SIGNAL ;
    ANTENNADIFFAREA 2.724000 ;
    PORT
      LAYER Metal2 ;
        RECT 30.040 215.060 30.440 215.460 ;
    END
  END N2BEGb[3]
  PIN N2BEGb[4]
    DIRECTION OUTPUT ;
    USE SIGNAL ;
    ANTENNADIFFAREA 2.724000 ;
    PORT
      LAYER Metal2 ;
        RECT 31.960 215.060 32.360 215.460 ;
    END
  END N2BEGb[4]
  PIN N2BEGb[5]
    DIRECTION OUTPUT ;
    USE SIGNAL ;
    ANTENNADIFFAREA 2.724000 ;
    PORT
      LAYER Metal2 ;
        RECT 33.880 215.060 34.280 215.460 ;
    END
  END N2BEGb[5]
  PIN N2BEGb[6]
    DIRECTION OUTPUT ;
    USE SIGNAL ;
    ANTENNADIFFAREA 2.724000 ;
    PORT
      LAYER Metal2 ;
        RECT 35.800 215.060 36.200 215.460 ;
    END
  END N2BEGb[6]
  PIN N2BEGb[7]
    DIRECTION OUTPUT ;
    USE SIGNAL ;
    ANTENNADIFFAREA 2.724000 ;
    PORT
      LAYER Metal2 ;
        RECT 37.720 215.060 38.120 215.460 ;
    END
  END N2BEGb[7]
  PIN N2END[0]
    DIRECTION INPUT ;
    USE SIGNAL ;
    ANTENNAGATEAREA 1.771400 ;
    PORT
      LAYER Metal2 ;
        RECT 24.280 0.000 24.680 0.400 ;
    END
  END N2END[0]
  PIN N2END[1]
    DIRECTION INPUT ;
    USE SIGNAL ;
    ANTENNAGATEAREA 1.534000 ;
    PORT
      LAYER Metal2 ;
        RECT 26.200 0.000 26.600 0.400 ;
    END
  END N2END[1]
  PIN N2END[2]
    DIRECTION INPUT ;
    USE SIGNAL ;
    ANTENNAGATEAREA 1.505400 ;
    PORT
      LAYER Metal2 ;
        RECT 28.120 0.000 28.520 0.400 ;
    END
  END N2END[2]
  PIN N2END[3]
    DIRECTION INPUT ;
    USE SIGNAL ;
    ANTENNAGATEAREA 1.705600 ;
    PORT
      LAYER Metal2 ;
        RECT 30.040 0.000 30.440 0.400 ;
    END
  END N2END[3]
  PIN N2END[4]
    DIRECTION INPUT ;
    USE SIGNAL ;
    ANTENNAGATEAREA 1.292200 ;
    PORT
      LAYER Metal2 ;
        RECT 31.960 0.000 32.360 0.400 ;
    END
  END N2END[4]
  PIN N2END[5]
    DIRECTION INPUT ;
    USE SIGNAL ;
    ANTENNAGATEAREA 1.079000 ;
    PORT
      LAYER Metal2 ;
        RECT 33.880 0.000 34.280 0.400 ;
    END
  END N2END[5]
  PIN N2END[6]
    DIRECTION INPUT ;
    USE SIGNAL ;
    ANTENNAGATEAREA 1.092000 ;
    PORT
      LAYER Metal2 ;
        RECT 35.800 0.000 36.200 0.400 ;
    END
  END N2END[6]
  PIN N2END[7]
    DIRECTION INPUT ;
    USE SIGNAL ;
    ANTENNAGATEAREA 1.362400 ;
    PORT
      LAYER Metal2 ;
        RECT 37.720 0.000 38.120 0.400 ;
    END
  END N2END[7]
  PIN N2MID[0]
    DIRECTION INPUT ;
    USE SIGNAL ;
    ANTENNAGATEAREA 0.886100 ;
    ANTENNADIFFAREA 8.061600 ;
    PORT
      LAYER Metal2 ;
        RECT 8.920 0.000 9.320 0.400 ;
    END
  END N2MID[0]
  PIN N2MID[1]
    DIRECTION INPUT ;
    USE SIGNAL ;
    ANTENNAGATEAREA 1.062100 ;
    PORT
      LAYER Metal2 ;
        RECT 10.840 0.000 11.240 0.400 ;
    END
  END N2MID[1]
  PIN N2MID[2]
    DIRECTION INPUT ;
    USE SIGNAL ;
    ANTENNAGATEAREA 0.848900 ;
    ANTENNADIFFAREA 32.246399 ;
    PORT
      LAYER Metal2 ;
        RECT 12.760 0.000 13.160 0.400 ;
    END
  END N2MID[2]
  PIN N2MID[3]
    DIRECTION INPUT ;
    USE SIGNAL ;
    ANTENNAGATEAREA 1.033500 ;
    PORT
      LAYER Metal2 ;
        RECT 14.680 0.000 15.080 0.400 ;
    END
  END N2MID[3]
  PIN N2MID[4]
    DIRECTION INPUT ;
    USE SIGNAL ;
    ANTENNAGATEAREA 0.833300 ;
    ANTENNADIFFAREA 16.123199 ;
    PORT
      LAYER Metal2 ;
        RECT 16.600 0.000 17.000 0.400 ;
    END
  END N2MID[4]
  PIN N2MID[5]
    DIRECTION INPUT ;
    USE SIGNAL ;
    ANTENNAGATEAREA 1.046500 ;
    PORT
      LAYER Metal2 ;
        RECT 18.520 0.000 18.920 0.400 ;
    END
  END N2MID[5]
  PIN N2MID[6]
    DIRECTION INPUT ;
    USE SIGNAL ;
    ANTENNAGATEAREA 0.820300 ;
    PORT
      LAYER Metal2 ;
        RECT 20.440 0.000 20.840 0.400 ;
    END
  END N2MID[6]
  PIN N2MID[7]
    DIRECTION INPUT ;
    USE SIGNAL ;
    ANTENNAGATEAREA 1.046500 ;
    PORT
      LAYER Metal2 ;
        RECT 22.360 0.000 22.760 0.400 ;
    END
  END N2MID[7]
  PIN N4BEG[0]
    DIRECTION OUTPUT ;
    USE SIGNAL ;
    ANTENNADIFFAREA 2.724000 ;
    PORT
      LAYER Metal2 ;
        RECT 40.600 215.060 41.000 215.460 ;
    END
  END N4BEG[0]
  PIN N4BEG[10]
    DIRECTION OUTPUT ;
    USE SIGNAL ;
    ANTENNADIFFAREA 2.724000 ;
    PORT
      LAYER Metal2 ;
        RECT 59.800 215.060 60.200 215.460 ;
    END
  END N4BEG[10]
  PIN N4BEG[11]
    DIRECTION OUTPUT ;
    USE SIGNAL ;
    ANTENNADIFFAREA 2.724000 ;
    PORT
      LAYER Metal2 ;
        RECT 61.720 215.060 62.120 215.460 ;
    END
  END N4BEG[11]
  PIN N4BEG[12]
    DIRECTION OUTPUT ;
    USE SIGNAL ;
    ANTENNADIFFAREA 2.724000 ;
    PORT
      LAYER Metal2 ;
        RECT 63.640 215.060 64.040 215.460 ;
    END
  END N4BEG[12]
  PIN N4BEG[13]
    DIRECTION OUTPUT ;
    USE SIGNAL ;
    ANTENNADIFFAREA 2.724000 ;
    PORT
      LAYER Metal2 ;
        RECT 65.560 215.060 65.960 215.460 ;
    END
  END N4BEG[13]
  PIN N4BEG[14]
    DIRECTION OUTPUT ;
    USE SIGNAL ;
    ANTENNADIFFAREA 2.724000 ;
    PORT
      LAYER Metal2 ;
        RECT 67.480 215.060 67.880 215.460 ;
    END
  END N4BEG[14]
  PIN N4BEG[15]
    DIRECTION OUTPUT ;
    USE SIGNAL ;
    ANTENNADIFFAREA 2.724000 ;
    PORT
      LAYER Metal2 ;
        RECT 69.400 215.060 69.800 215.460 ;
    END
  END N4BEG[15]
  PIN N4BEG[1]
    DIRECTION OUTPUT ;
    USE SIGNAL ;
    ANTENNADIFFAREA 2.724000 ;
    PORT
      LAYER Metal2 ;
        RECT 42.520 215.060 42.920 215.460 ;
    END
  END N4BEG[1]
  PIN N4BEG[2]
    DIRECTION OUTPUT ;
    USE SIGNAL ;
    ANTENNADIFFAREA 2.724000 ;
    PORT
      LAYER Metal2 ;
        RECT 44.440 215.060 44.840 215.460 ;
    END
  END N4BEG[2]
  PIN N4BEG[3]
    DIRECTION OUTPUT ;
    USE SIGNAL ;
    ANTENNADIFFAREA 2.724000 ;
    PORT
      LAYER Metal2 ;
        RECT 46.360 215.060 46.760 215.460 ;
    END
  END N4BEG[3]
  PIN N4BEG[4]
    DIRECTION OUTPUT ;
    USE SIGNAL ;
    ANTENNADIFFAREA 2.724000 ;
    PORT
      LAYER Metal2 ;
        RECT 48.280 215.060 48.680 215.460 ;
    END
  END N4BEG[4]
  PIN N4BEG[5]
    DIRECTION OUTPUT ;
    USE SIGNAL ;
    ANTENNADIFFAREA 2.724000 ;
    PORT
      LAYER Metal2 ;
        RECT 50.200 215.060 50.600 215.460 ;
    END
  END N4BEG[5]
  PIN N4BEG[6]
    DIRECTION OUTPUT ;
    USE SIGNAL ;
    ANTENNADIFFAREA 2.724000 ;
    PORT
      LAYER Metal2 ;
        RECT 52.120 215.060 52.520 215.460 ;
    END
  END N4BEG[6]
  PIN N4BEG[7]
    DIRECTION OUTPUT ;
    USE SIGNAL ;
    ANTENNADIFFAREA 2.724000 ;
    PORT
      LAYER Metal2 ;
        RECT 54.040 215.060 54.440 215.460 ;
    END
  END N4BEG[7]
  PIN N4BEG[8]
    DIRECTION OUTPUT ;
    USE SIGNAL ;
    ANTENNADIFFAREA 2.724000 ;
    PORT
      LAYER Metal2 ;
        RECT 55.960 215.060 56.360 215.460 ;
    END
  END N4BEG[8]
  PIN N4BEG[9]
    DIRECTION OUTPUT ;
    USE SIGNAL ;
    ANTENNADIFFAREA 2.724000 ;
    PORT
      LAYER Metal2 ;
        RECT 57.880 215.060 58.280 215.460 ;
    END
  END N4BEG[9]
  PIN N4END[0]
    DIRECTION INPUT ;
    USE SIGNAL ;
    ANTENNAGATEAREA 1.059500 ;
    PORT
      LAYER Metal2 ;
        RECT 40.600 0.000 41.000 0.400 ;
    END
  END N4END[0]
  PIN N4END[10]
    DIRECTION INPUT ;
    USE SIGNAL ;
    ANTENNAGATEAREA 0.180700 ;
    PORT
      LAYER Metal2 ;
        RECT 59.800 0.000 60.200 0.400 ;
    END
  END N4END[10]
  PIN N4END[11]
    DIRECTION INPUT ;
    USE SIGNAL ;
    ANTENNAGATEAREA 0.180700 ;
    PORT
      LAYER Metal2 ;
        RECT 61.720 0.000 62.120 0.400 ;
    END
  END N4END[11]
  PIN N4END[12]
    DIRECTION INPUT ;
    USE SIGNAL ;
    ANTENNAGATEAREA 0.180700 ;
    PORT
      LAYER Metal2 ;
        RECT 63.640 0.000 64.040 0.400 ;
    END
  END N4END[12]
  PIN N4END[13]
    DIRECTION INPUT ;
    USE SIGNAL ;
    ANTENNAGATEAREA 0.180700 ;
    PORT
      LAYER Metal2 ;
        RECT 65.560 0.000 65.960 0.400 ;
    END
  END N4END[13]
  PIN N4END[14]
    DIRECTION INPUT ;
    USE SIGNAL ;
    ANTENNAGATEAREA 0.180700 ;
    PORT
      LAYER Metal2 ;
        RECT 67.480 0.000 67.880 0.400 ;
    END
  END N4END[14]
  PIN N4END[15]
    DIRECTION INPUT ;
    USE SIGNAL ;
    ANTENNAGATEAREA 0.180700 ;
    PORT
      LAYER Metal2 ;
        RECT 69.400 0.000 69.800 0.400 ;
    END
  END N4END[15]
  PIN N4END[1]
    DIRECTION INPUT ;
    USE SIGNAL ;
    ANTENNAGATEAREA 0.668200 ;
    PORT
      LAYER Metal2 ;
        RECT 42.520 0.000 42.920 0.400 ;
    END
  END N4END[1]
  PIN N4END[2]
    DIRECTION INPUT ;
    USE SIGNAL ;
    ANTENNAGATEAREA 1.092000 ;
    PORT
      LAYER Metal2 ;
        RECT 44.440 0.000 44.840 0.400 ;
    END
  END N4END[2]
  PIN N4END[3]
    DIRECTION INPUT ;
    USE SIGNAL ;
    ANTENNAGATEAREA 0.968500 ;
    PORT
      LAYER Metal2 ;
        RECT 46.360 0.000 46.760 0.400 ;
    END
  END N4END[3]
  PIN N4END[4]
    DIRECTION INPUT ;
    USE SIGNAL ;
    ANTENNAGATEAREA 0.180700 ;
    PORT
      LAYER Metal2 ;
        RECT 48.280 0.000 48.680 0.400 ;
    END
  END N4END[4]
  PIN N4END[5]
    DIRECTION INPUT ;
    USE SIGNAL ;
    ANTENNAGATEAREA 0.180700 ;
    PORT
      LAYER Metal2 ;
        RECT 50.200 0.000 50.600 0.400 ;
    END
  END N4END[5]
  PIN N4END[6]
    DIRECTION INPUT ;
    USE SIGNAL ;
    ANTENNAGATEAREA 0.180700 ;
    PORT
      LAYER Metal2 ;
        RECT 52.120 0.000 52.520 0.400 ;
    END
  END N4END[6]
  PIN N4END[7]
    DIRECTION INPUT ;
    USE SIGNAL ;
    ANTENNAGATEAREA 0.180700 ;
    PORT
      LAYER Metal2 ;
        RECT 54.040 0.000 54.440 0.400 ;
    END
  END N4END[7]
  PIN N4END[8]
    DIRECTION INPUT ;
    USE SIGNAL ;
    ANTENNAGATEAREA 0.180700 ;
    PORT
      LAYER Metal2 ;
        RECT 55.960 0.000 56.360 0.400 ;
    END
  END N4END[8]
  PIN N4END[9]
    DIRECTION INPUT ;
    USE SIGNAL ;
    ANTENNAGATEAREA 0.180700 ;
    PORT
      LAYER Metal2 ;
        RECT 57.880 0.000 58.280 0.400 ;
    END
  END N4END[9]
  PIN NN4BEG[0]
    DIRECTION OUTPUT ;
    USE SIGNAL ;
    ANTENNADIFFAREA 2.724000 ;
    PORT
      LAYER Metal2 ;
        RECT 72.280 215.060 72.680 215.460 ;
    END
  END NN4BEG[0]
  PIN NN4BEG[10]
    DIRECTION OUTPUT ;
    USE SIGNAL ;
    ANTENNADIFFAREA 2.724000 ;
    PORT
      LAYER Metal2 ;
        RECT 91.480 215.060 91.880 215.460 ;
    END
  END NN4BEG[10]
  PIN NN4BEG[11]
    DIRECTION OUTPUT ;
    USE SIGNAL ;
    ANTENNADIFFAREA 2.724000 ;
    PORT
      LAYER Metal2 ;
        RECT 93.400 215.060 93.800 215.460 ;
    END
  END NN4BEG[11]
  PIN NN4BEG[12]
    DIRECTION OUTPUT ;
    USE SIGNAL ;
    ANTENNADIFFAREA 2.724000 ;
    PORT
      LAYER Metal2 ;
        RECT 95.320 215.060 95.720 215.460 ;
    END
  END NN4BEG[12]
  PIN NN4BEG[13]
    DIRECTION OUTPUT ;
    USE SIGNAL ;
    ANTENNADIFFAREA 2.724000 ;
    PORT
      LAYER Metal2 ;
        RECT 97.240 215.060 97.640 215.460 ;
    END
  END NN4BEG[13]
  PIN NN4BEG[14]
    DIRECTION OUTPUT ;
    USE SIGNAL ;
    ANTENNADIFFAREA 2.724000 ;
    PORT
      LAYER Metal2 ;
        RECT 99.160 215.060 99.560 215.460 ;
    END
  END NN4BEG[14]
  PIN NN4BEG[15]
    DIRECTION OUTPUT ;
    USE SIGNAL ;
    ANTENNADIFFAREA 2.724000 ;
    PORT
      LAYER Metal2 ;
        RECT 101.080 215.060 101.480 215.460 ;
    END
  END NN4BEG[15]
  PIN NN4BEG[1]
    DIRECTION OUTPUT ;
    USE SIGNAL ;
    ANTENNADIFFAREA 2.724000 ;
    PORT
      LAYER Metal2 ;
        RECT 74.200 215.060 74.600 215.460 ;
    END
  END NN4BEG[1]
  PIN NN4BEG[2]
    DIRECTION OUTPUT ;
    USE SIGNAL ;
    ANTENNADIFFAREA 2.724000 ;
    PORT
      LAYER Metal2 ;
        RECT 76.120 215.060 76.520 215.460 ;
    END
  END NN4BEG[2]
  PIN NN4BEG[3]
    DIRECTION OUTPUT ;
    USE SIGNAL ;
    ANTENNADIFFAREA 2.724000 ;
    PORT
      LAYER Metal2 ;
        RECT 78.040 215.060 78.440 215.460 ;
    END
  END NN4BEG[3]
  PIN NN4BEG[4]
    DIRECTION OUTPUT ;
    USE SIGNAL ;
    ANTENNADIFFAREA 2.724000 ;
    PORT
      LAYER Metal2 ;
        RECT 79.960 215.060 80.360 215.460 ;
    END
  END NN4BEG[4]
  PIN NN4BEG[5]
    DIRECTION OUTPUT ;
    USE SIGNAL ;
    ANTENNADIFFAREA 2.724000 ;
    PORT
      LAYER Metal2 ;
        RECT 81.880 215.060 82.280 215.460 ;
    END
  END NN4BEG[5]
  PIN NN4BEG[6]
    DIRECTION OUTPUT ;
    USE SIGNAL ;
    ANTENNADIFFAREA 2.724000 ;
    PORT
      LAYER Metal2 ;
        RECT 83.800 215.060 84.200 215.460 ;
    END
  END NN4BEG[6]
  PIN NN4BEG[7]
    DIRECTION OUTPUT ;
    USE SIGNAL ;
    ANTENNADIFFAREA 2.724000 ;
    PORT
      LAYER Metal2 ;
        RECT 85.720 215.060 86.120 215.460 ;
    END
  END NN4BEG[7]
  PIN NN4BEG[8]
    DIRECTION OUTPUT ;
    USE SIGNAL ;
    ANTENNADIFFAREA 2.724000 ;
    PORT
      LAYER Metal2 ;
        RECT 87.640 215.060 88.040 215.460 ;
    END
  END NN4BEG[8]
  PIN NN4BEG[9]
    DIRECTION OUTPUT ;
    USE SIGNAL ;
    ANTENNADIFFAREA 2.724000 ;
    PORT
      LAYER Metal2 ;
        RECT 89.560 215.060 89.960 215.460 ;
    END
  END NN4BEG[9]
  PIN NN4END[0]
    DIRECTION INPUT ;
    USE SIGNAL ;
    ANTENNAGATEAREA 1.107600 ;
    PORT
      LAYER Metal2 ;
        RECT 72.280 0.000 72.680 0.400 ;
    END
  END NN4END[0]
  PIN NN4END[10]
    DIRECTION INPUT ;
    USE SIGNAL ;
    ANTENNAGATEAREA 0.180700 ;
    PORT
      LAYER Metal2 ;
        RECT 91.480 0.000 91.880 0.400 ;
    END
  END NN4END[10]
  PIN NN4END[11]
    DIRECTION INPUT ;
    USE SIGNAL ;
    ANTENNAGATEAREA 0.180700 ;
    PORT
      LAYER Metal2 ;
        RECT 93.400 0.000 93.800 0.400 ;
    END
  END NN4END[11]
  PIN NN4END[12]
    DIRECTION INPUT ;
    USE SIGNAL ;
    ANTENNAGATEAREA 0.180700 ;
    PORT
      LAYER Metal2 ;
        RECT 95.320 0.000 95.720 0.400 ;
    END
  END NN4END[12]
  PIN NN4END[13]
    DIRECTION INPUT ;
    USE SIGNAL ;
    ANTENNAGATEAREA 0.180700 ;
    PORT
      LAYER Metal2 ;
        RECT 97.240 0.000 97.640 0.400 ;
    END
  END NN4END[13]
  PIN NN4END[14]
    DIRECTION INPUT ;
    USE SIGNAL ;
    ANTENNAGATEAREA 0.180700 ;
    PORT
      LAYER Metal2 ;
        RECT 99.160 0.000 99.560 0.400 ;
    END
  END NN4END[14]
  PIN NN4END[15]
    DIRECTION INPUT ;
    USE SIGNAL ;
    ANTENNAGATEAREA 0.180700 ;
    PORT
      LAYER Metal2 ;
        RECT 101.080 0.000 101.480 0.400 ;
    END
  END NN4END[15]
  PIN NN4END[1]
    DIRECTION INPUT ;
    USE SIGNAL ;
    ANTENNAGATEAREA 1.059500 ;
    PORT
      LAYER Metal2 ;
        RECT 74.200 0.000 74.600 0.400 ;
    END
  END NN4END[1]
  PIN NN4END[2]
    DIRECTION INPUT ;
    USE SIGNAL ;
    ANTENNAGATEAREA 1.120600 ;
    PORT
      LAYER Metal2 ;
        RECT 76.120 0.000 76.520 0.400 ;
    END
  END NN4END[2]
  PIN NN4END[3]
    DIRECTION INPUT ;
    USE SIGNAL ;
    ANTENNAGATEAREA 1.066000 ;
    PORT
      LAYER Metal2 ;
        RECT 78.040 0.000 78.440 0.400 ;
    END
  END NN4END[3]
  PIN NN4END[4]
    DIRECTION INPUT ;
    USE SIGNAL ;
    ANTENNAGATEAREA 0.180700 ;
    PORT
      LAYER Metal2 ;
        RECT 79.960 0.000 80.360 0.400 ;
    END
  END NN4END[4]
  PIN NN4END[5]
    DIRECTION INPUT ;
    USE SIGNAL ;
    ANTENNAGATEAREA 0.180700 ;
    PORT
      LAYER Metal2 ;
        RECT 81.880 0.000 82.280 0.400 ;
    END
  END NN4END[5]
  PIN NN4END[6]
    DIRECTION INPUT ;
    USE SIGNAL ;
    ANTENNAGATEAREA 0.180700 ;
    PORT
      LAYER Metal2 ;
        RECT 83.800 0.000 84.200 0.400 ;
    END
  END NN4END[6]
  PIN NN4END[7]
    DIRECTION INPUT ;
    USE SIGNAL ;
    ANTENNAGATEAREA 0.180700 ;
    PORT
      LAYER Metal2 ;
        RECT 85.720 0.000 86.120 0.400 ;
    END
  END NN4END[7]
  PIN NN4END[8]
    DIRECTION INPUT ;
    USE SIGNAL ;
    ANTENNAGATEAREA 0.180700 ;
    PORT
      LAYER Metal2 ;
        RECT 87.640 0.000 88.040 0.400 ;
    END
  END NN4END[8]
  PIN NN4END[9]
    DIRECTION INPUT ;
    USE SIGNAL ;
    ANTENNAGATEAREA 0.180700 ;
    PORT
      LAYER Metal2 ;
        RECT 89.560 0.000 89.960 0.400 ;
    END
  END NN4END[9]
  PIN S1BEG[0]
    DIRECTION OUTPUT ;
    USE SIGNAL ;
    ANTENNADIFFAREA 2.724000 ;
    PORT
      LAYER Metal2 ;
        RECT 103.000 0.000 103.400 0.400 ;
    END
  END S1BEG[0]
  PIN S1BEG[1]
    DIRECTION OUTPUT ;
    USE SIGNAL ;
    ANTENNADIFFAREA 2.724000 ;
    PORT
      LAYER Metal2 ;
        RECT 104.920 0.000 105.320 0.400 ;
    END
  END S1BEG[1]
  PIN S1BEG[2]
    DIRECTION OUTPUT ;
    USE SIGNAL ;
    ANTENNADIFFAREA 2.724000 ;
    PORT
      LAYER Metal2 ;
        RECT 106.840 0.000 107.240 0.400 ;
    END
  END S1BEG[2]
  PIN S1BEG[3]
    DIRECTION OUTPUT ;
    USE SIGNAL ;
    ANTENNADIFFAREA 2.724000 ;
    PORT
      LAYER Metal2 ;
        RECT 108.760 0.000 109.160 0.400 ;
    END
  END S1BEG[3]
  PIN S1END[0]
    DIRECTION INPUT ;
    USE SIGNAL ;
    ANTENNAGATEAREA 1.718600 ;
    PORT
      LAYER Metal2 ;
        RECT 103.000 215.060 103.400 215.460 ;
    END
  END S1END[0]
  PIN S1END[1]
    DIRECTION INPUT ;
    USE SIGNAL ;
    ANTENNAGATEAREA 1.760200 ;
    PORT
      LAYER Metal2 ;
        RECT 104.920 215.060 105.320 215.460 ;
    END
  END S1END[1]
  PIN S1END[2]
    DIRECTION INPUT ;
    USE SIGNAL ;
    ANTENNAGATEAREA 1.773200 ;
    PORT
      LAYER Metal2 ;
        RECT 106.840 215.060 107.240 215.460 ;
    END
  END S1END[2]
  PIN S1END[3]
    DIRECTION INPUT ;
    USE SIGNAL ;
    ANTENNAGATEAREA 1.625000 ;
    PORT
      LAYER Metal2 ;
        RECT 108.760 215.060 109.160 215.460 ;
    END
  END S1END[3]
  PIN S2BEG[0]
    DIRECTION OUTPUT ;
    USE SIGNAL ;
    ANTENNADIFFAREA 2.724000 ;
    PORT
      LAYER Metal2 ;
        RECT 111.640 0.000 112.040 0.400 ;
    END
  END S2BEG[0]
  PIN S2BEG[1]
    DIRECTION OUTPUT ;
    USE SIGNAL ;
    ANTENNADIFFAREA 2.724000 ;
    PORT
      LAYER Metal2 ;
        RECT 113.560 0.000 113.960 0.400 ;
    END
  END S2BEG[1]
  PIN S2BEG[2]
    DIRECTION OUTPUT ;
    USE SIGNAL ;
    ANTENNADIFFAREA 2.724000 ;
    PORT
      LAYER Metal2 ;
        RECT 115.480 0.000 115.880 0.400 ;
    END
  END S2BEG[2]
  PIN S2BEG[3]
    DIRECTION OUTPUT ;
    USE SIGNAL ;
    ANTENNADIFFAREA 2.724000 ;
    PORT
      LAYER Metal2 ;
        RECT 117.400 0.000 117.800 0.400 ;
    END
  END S2BEG[3]
  PIN S2BEG[4]
    DIRECTION OUTPUT ;
    USE SIGNAL ;
    ANTENNADIFFAREA 2.724000 ;
    PORT
      LAYER Metal2 ;
        RECT 119.320 0.000 119.720 0.400 ;
    END
  END S2BEG[4]
  PIN S2BEG[5]
    DIRECTION OUTPUT ;
    USE SIGNAL ;
    ANTENNADIFFAREA 2.724000 ;
    PORT
      LAYER Metal2 ;
        RECT 121.240 0.000 121.640 0.400 ;
    END
  END S2BEG[5]
  PIN S2BEG[6]
    DIRECTION OUTPUT ;
    USE SIGNAL ;
    ANTENNADIFFAREA 2.724000 ;
    PORT
      LAYER Metal2 ;
        RECT 123.160 0.000 123.560 0.400 ;
    END
  END S2BEG[6]
  PIN S2BEG[7]
    DIRECTION OUTPUT ;
    USE SIGNAL ;
    ANTENNADIFFAREA 2.724000 ;
    PORT
      LAYER Metal2 ;
        RECT 125.080 0.000 125.480 0.400 ;
    END
  END S2BEG[7]
  PIN S2BEGb[0]
    DIRECTION OUTPUT ;
    USE SIGNAL ;
    ANTENNADIFFAREA 2.724000 ;
    PORT
      LAYER Metal2 ;
        RECT 127.000 0.000 127.400 0.400 ;
    END
  END S2BEGb[0]
  PIN S2BEGb[1]
    DIRECTION OUTPUT ;
    USE SIGNAL ;
    ANTENNADIFFAREA 2.724000 ;
    PORT
      LAYER Metal2 ;
        RECT 128.920 0.000 129.320 0.400 ;
    END
  END S2BEGb[1]
  PIN S2BEGb[2]
    DIRECTION OUTPUT ;
    USE SIGNAL ;
    ANTENNADIFFAREA 2.724000 ;
    PORT
      LAYER Metal2 ;
        RECT 130.840 0.000 131.240 0.400 ;
    END
  END S2BEGb[2]
  PIN S2BEGb[3]
    DIRECTION OUTPUT ;
    USE SIGNAL ;
    ANTENNADIFFAREA 2.724000 ;
    PORT
      LAYER Metal2 ;
        RECT 132.760 0.000 133.160 0.400 ;
    END
  END S2BEGb[3]
  PIN S2BEGb[4]
    DIRECTION OUTPUT ;
    USE SIGNAL ;
    ANTENNADIFFAREA 2.724000 ;
    PORT
      LAYER Metal2 ;
        RECT 134.680 0.000 135.080 0.400 ;
    END
  END S2BEGb[4]
  PIN S2BEGb[5]
    DIRECTION OUTPUT ;
    USE SIGNAL ;
    ANTENNADIFFAREA 2.724000 ;
    PORT
      LAYER Metal2 ;
        RECT 136.600 0.000 137.000 0.400 ;
    END
  END S2BEGb[5]
  PIN S2BEGb[6]
    DIRECTION OUTPUT ;
    USE SIGNAL ;
    ANTENNADIFFAREA 2.724000 ;
    PORT
      LAYER Metal2 ;
        RECT 138.520 0.000 138.920 0.400 ;
    END
  END S2BEGb[6]
  PIN S2BEGb[7]
    DIRECTION OUTPUT ;
    USE SIGNAL ;
    ANTENNADIFFAREA 2.724000 ;
    PORT
      LAYER Metal2 ;
        RECT 140.440 0.000 140.840 0.400 ;
    END
  END S2BEGb[7]
  PIN S2END[0]
    DIRECTION INPUT ;
    USE SIGNAL ;
    ANTENNAGATEAREA 1.666600 ;
    PORT
      LAYER Metal2 ;
        RECT 127.000 215.060 127.400 215.460 ;
    END
  END S2END[0]
  PIN S2END[1]
    DIRECTION INPUT ;
    USE SIGNAL ;
    ANTENNAGATEAREA 1.813000 ;
    PORT
      LAYER Metal2 ;
        RECT 128.920 215.060 129.320 215.460 ;
    END
  END S2END[1]
  PIN S2END[2]
    DIRECTION INPUT ;
    USE SIGNAL ;
    ANTENNAGATEAREA 1.760200 ;
    PORT
      LAYER Metal2 ;
        RECT 130.840 215.060 131.240 215.460 ;
    END
  END S2END[2]
  PIN S2END[3]
    DIRECTION INPUT ;
    USE SIGNAL ;
    ANTENNAGATEAREA 1.492400 ;
    PORT
      LAYER Metal2 ;
        RECT 132.760 215.060 133.160 215.460 ;
    END
  END S2END[3]
  PIN S2END[4]
    DIRECTION INPUT ;
    USE SIGNAL ;
    ANTENNAGATEAREA 1.079000 ;
    PORT
      LAYER Metal2 ;
        RECT 134.680 215.060 135.080 215.460 ;
    END
  END S2END[4]
  PIN S2END[5]
    DIRECTION INPUT ;
    USE SIGNAL ;
    ANTENNAGATEAREA 1.092000 ;
    PORT
      LAYER Metal2 ;
        RECT 136.600 215.060 137.000 215.460 ;
    END
  END S2END[5]
  PIN S2END[6]
    DIRECTION INPUT ;
    USE SIGNAL ;
    ANTENNAGATEAREA 1.120600 ;
    PORT
      LAYER Metal2 ;
        RECT 138.520 215.060 138.920 215.460 ;
    END
  END S2END[6]
  PIN S2END[7]
    DIRECTION INPUT ;
    USE SIGNAL ;
    ANTENNAGATEAREA 1.362400 ;
    PORT
      LAYER Metal2 ;
        RECT 140.440 215.060 140.840 215.460 ;
    END
  END S2END[7]
  PIN S2MID[0]
    DIRECTION INPUT ;
    USE SIGNAL ;
    ANTENNAGATEAREA 0.848900 ;
    PORT
      LAYER Metal2 ;
        RECT 111.640 215.060 112.040 215.460 ;
    END
  END S2MID[0]
  PIN S2MID[1]
    DIRECTION INPUT ;
    USE SIGNAL ;
    ANTENNAGATEAREA 1.099300 ;
    PORT
      LAYER Metal2 ;
        RECT 113.560 215.060 113.960 215.460 ;
    END
  END S2MID[1]
  PIN S2MID[2]
    DIRECTION INPUT ;
    USE SIGNAL ;
    ANTENNAGATEAREA 0.848900 ;
    PORT
      LAYER Metal2 ;
        RECT 115.480 215.060 115.880 215.460 ;
    END
  END S2MID[2]
  PIN S2MID[3]
    DIRECTION INPUT ;
    USE SIGNAL ;
    ANTENNAGATEAREA 1.033500 ;
    ANTENNADIFFAREA 10.077000 ;
    PORT
      LAYER Metal2 ;
        RECT 117.400 215.060 117.800 215.460 ;
    END
  END S2MID[3]
  PIN S2MID[4]
    DIRECTION INPUT ;
    USE SIGNAL ;
    ANTENNAGATEAREA 0.820300 ;
    PORT
      LAYER Metal2 ;
        RECT 119.320 215.060 119.720 215.460 ;
    END
  END S2MID[4]
  PIN S2MID[5]
    DIRECTION INPUT ;
    USE SIGNAL ;
    ANTENNAGATEAREA 1.062100 ;
    PORT
      LAYER Metal2 ;
        RECT 121.240 215.060 121.640 215.460 ;
    END
  END S2MID[5]
  PIN S2MID[6]
    DIRECTION INPUT ;
    USE SIGNAL ;
    ANTENNAGATEAREA 0.820300 ;
    PORT
      LAYER Metal2 ;
        RECT 123.160 215.060 123.560 215.460 ;
    END
  END S2MID[6]
  PIN S2MID[7]
    DIRECTION INPUT ;
    USE SIGNAL ;
    ANTENNAGATEAREA 1.001000 ;
    PORT
      LAYER Metal2 ;
        RECT 125.080 215.060 125.480 215.460 ;
    END
  END S2MID[7]
  PIN S4BEG[0]
    DIRECTION OUTPUT ;
    USE SIGNAL ;
    ANTENNADIFFAREA 2.724000 ;
    PORT
      LAYER Metal2 ;
        RECT 143.320 0.000 143.720 0.400 ;
    END
  END S4BEG[0]
  PIN S4BEG[10]
    DIRECTION OUTPUT ;
    USE SIGNAL ;
    ANTENNADIFFAREA 2.724000 ;
    PORT
      LAYER Metal2 ;
        RECT 162.520 0.000 162.920 0.400 ;
    END
  END S4BEG[10]
  PIN S4BEG[11]
    DIRECTION OUTPUT ;
    USE SIGNAL ;
    ANTENNADIFFAREA 2.724000 ;
    PORT
      LAYER Metal2 ;
        RECT 164.440 0.000 164.840 0.400 ;
    END
  END S4BEG[11]
  PIN S4BEG[12]
    DIRECTION OUTPUT ;
    USE SIGNAL ;
    ANTENNADIFFAREA 2.724000 ;
    PORT
      LAYER Metal2 ;
        RECT 166.360 0.000 166.760 0.400 ;
    END
  END S4BEG[12]
  PIN S4BEG[13]
    DIRECTION OUTPUT ;
    USE SIGNAL ;
    ANTENNADIFFAREA 2.724000 ;
    PORT
      LAYER Metal2 ;
        RECT 168.280 0.000 168.680 0.400 ;
    END
  END S4BEG[13]
  PIN S4BEG[14]
    DIRECTION OUTPUT ;
    USE SIGNAL ;
    ANTENNADIFFAREA 2.724000 ;
    PORT
      LAYER Metal2 ;
        RECT 170.200 0.000 170.600 0.400 ;
    END
  END S4BEG[14]
  PIN S4BEG[15]
    DIRECTION OUTPUT ;
    USE SIGNAL ;
    ANTENNADIFFAREA 2.724000 ;
    PORT
      LAYER Metal2 ;
        RECT 172.120 0.000 172.520 0.400 ;
    END
  END S4BEG[15]
  PIN S4BEG[1]
    DIRECTION OUTPUT ;
    USE SIGNAL ;
    ANTENNADIFFAREA 2.724000 ;
    PORT
      LAYER Metal2 ;
        RECT 145.240 0.000 145.640 0.400 ;
    END
  END S4BEG[1]
  PIN S4BEG[2]
    DIRECTION OUTPUT ;
    USE SIGNAL ;
    ANTENNADIFFAREA 2.724000 ;
    PORT
      LAYER Metal2 ;
        RECT 147.160 0.000 147.560 0.400 ;
    END
  END S4BEG[2]
  PIN S4BEG[3]
    DIRECTION OUTPUT ;
    USE SIGNAL ;
    ANTENNADIFFAREA 2.724000 ;
    PORT
      LAYER Metal2 ;
        RECT 149.080 0.000 149.480 0.400 ;
    END
  END S4BEG[3]
  PIN S4BEG[4]
    DIRECTION OUTPUT ;
    USE SIGNAL ;
    ANTENNADIFFAREA 2.724000 ;
    PORT
      LAYER Metal2 ;
        RECT 151.000 0.000 151.400 0.400 ;
    END
  END S4BEG[4]
  PIN S4BEG[5]
    DIRECTION OUTPUT ;
    USE SIGNAL ;
    ANTENNADIFFAREA 2.724000 ;
    PORT
      LAYER Metal2 ;
        RECT 152.920 0.000 153.320 0.400 ;
    END
  END S4BEG[5]
  PIN S4BEG[6]
    DIRECTION OUTPUT ;
    USE SIGNAL ;
    ANTENNADIFFAREA 2.724000 ;
    PORT
      LAYER Metal2 ;
        RECT 154.840 0.000 155.240 0.400 ;
    END
  END S4BEG[6]
  PIN S4BEG[7]
    DIRECTION OUTPUT ;
    USE SIGNAL ;
    ANTENNADIFFAREA 2.724000 ;
    PORT
      LAYER Metal2 ;
        RECT 156.760 0.000 157.160 0.400 ;
    END
  END S4BEG[7]
  PIN S4BEG[8]
    DIRECTION OUTPUT ;
    USE SIGNAL ;
    ANTENNADIFFAREA 2.724000 ;
    PORT
      LAYER Metal2 ;
        RECT 158.680 0.000 159.080 0.400 ;
    END
  END S4BEG[8]
  PIN S4BEG[9]
    DIRECTION OUTPUT ;
    USE SIGNAL ;
    ANTENNADIFFAREA 2.724000 ;
    PORT
      LAYER Metal2 ;
        RECT 160.600 0.000 161.000 0.400 ;
    END
  END S4BEG[9]
  PIN S4END[0]
    DIRECTION INPUT ;
    USE SIGNAL ;
    ANTENNAGATEAREA 1.160400 ;
    PORT
      LAYER Metal2 ;
        RECT 143.320 215.060 143.720 215.460 ;
    END
  END S4END[0]
  PIN S4END[10]
    DIRECTION INPUT ;
    USE SIGNAL ;
    ANTENNAGATEAREA 0.180700 ;
    PORT
      LAYER Metal2 ;
        RECT 162.520 215.060 162.920 215.460 ;
    END
  END S4END[10]
  PIN S4END[11]
    DIRECTION INPUT ;
    USE SIGNAL ;
    ANTENNAGATEAREA 0.180700 ;
    PORT
      LAYER Metal2 ;
        RECT 164.440 215.060 164.840 215.460 ;
    END
  END S4END[11]
  PIN S4END[12]
    DIRECTION INPUT ;
    USE SIGNAL ;
    ANTENNAGATEAREA 0.180700 ;
    PORT
      LAYER Metal2 ;
        RECT 166.360 215.060 166.760 215.460 ;
    END
  END S4END[12]
  PIN S4END[13]
    DIRECTION INPUT ;
    USE SIGNAL ;
    ANTENNAGATEAREA 0.180700 ;
    PORT
      LAYER Metal2 ;
        RECT 168.280 215.060 168.680 215.460 ;
    END
  END S4END[13]
  PIN S4END[14]
    DIRECTION INPUT ;
    USE SIGNAL ;
    ANTENNAGATEAREA 0.180700 ;
    PORT
      LAYER Metal2 ;
        RECT 170.200 215.060 170.600 215.460 ;
    END
  END S4END[14]
  PIN S4END[15]
    DIRECTION INPUT ;
    USE SIGNAL ;
    ANTENNAGATEAREA 0.180700 ;
    PORT
      LAYER Metal2 ;
        RECT 172.120 215.060 172.520 215.460 ;
    END
  END S4END[15]
  PIN S4END[1]
    DIRECTION INPUT ;
    USE SIGNAL ;
    ANTENNAGATEAREA 1.094600 ;
    ANTENNADIFFAREA 10.077000 ;
    PORT
      LAYER Metal2 ;
        RECT 145.240 215.060 145.640 215.460 ;
    END
  END S4END[1]
  PIN S4END[2]
    DIRECTION INPUT ;
    USE SIGNAL ;
    ANTENNAGATEAREA 1.131800 ;
    PORT
      LAYER Metal2 ;
        RECT 147.160 215.060 147.560 215.460 ;
    END
  END S4END[2]
  PIN S4END[3]
    DIRECTION INPUT ;
    USE SIGNAL ;
    ANTENNAGATEAREA 1.112300 ;
    PORT
      LAYER Metal2 ;
        RECT 149.080 215.060 149.480 215.460 ;
    END
  END S4END[3]
  PIN S4END[4]
    DIRECTION INPUT ;
    USE SIGNAL ;
    ANTENNAGATEAREA 0.180700 ;
    PORT
      LAYER Metal2 ;
        RECT 151.000 215.060 151.400 215.460 ;
    END
  END S4END[4]
  PIN S4END[5]
    DIRECTION INPUT ;
    USE SIGNAL ;
    ANTENNAGATEAREA 0.180700 ;
    PORT
      LAYER Metal2 ;
        RECT 152.920 215.060 153.320 215.460 ;
    END
  END S4END[5]
  PIN S4END[6]
    DIRECTION INPUT ;
    USE SIGNAL ;
    ANTENNAGATEAREA 0.180700 ;
    PORT
      LAYER Metal2 ;
        RECT 154.840 215.060 155.240 215.460 ;
    END
  END S4END[6]
  PIN S4END[7]
    DIRECTION INPUT ;
    USE SIGNAL ;
    ANTENNAGATEAREA 0.180700 ;
    PORT
      LAYER Metal2 ;
        RECT 156.760 215.060 157.160 215.460 ;
    END
  END S4END[7]
  PIN S4END[8]
    DIRECTION INPUT ;
    USE SIGNAL ;
    ANTENNAGATEAREA 0.180700 ;
    PORT
      LAYER Metal2 ;
        RECT 158.680 215.060 159.080 215.460 ;
    END
  END S4END[8]
  PIN S4END[9]
    DIRECTION INPUT ;
    USE SIGNAL ;
    ANTENNAGATEAREA 0.180700 ;
    PORT
      LAYER Metal2 ;
        RECT 160.600 215.060 161.000 215.460 ;
    END
  END S4END[9]
  PIN SS4BEG[0]
    DIRECTION OUTPUT ;
    USE SIGNAL ;
    ANTENNADIFFAREA 2.724000 ;
    PORT
      LAYER Metal2 ;
        RECT 175.000 0.000 175.400 0.400 ;
    END
  END SS4BEG[0]
  PIN SS4BEG[10]
    DIRECTION OUTPUT ;
    USE SIGNAL ;
    ANTENNADIFFAREA 2.724000 ;
    PORT
      LAYER Metal2 ;
        RECT 194.200 0.000 194.600 0.400 ;
    END
  END SS4BEG[10]
  PIN SS4BEG[11]
    DIRECTION OUTPUT ;
    USE SIGNAL ;
    ANTENNADIFFAREA 2.724000 ;
    PORT
      LAYER Metal2 ;
        RECT 196.120 0.000 196.520 0.400 ;
    END
  END SS4BEG[11]
  PIN SS4BEG[12]
    DIRECTION OUTPUT ;
    USE SIGNAL ;
    ANTENNADIFFAREA 2.724000 ;
    PORT
      LAYER Metal2 ;
        RECT 198.040 0.000 198.440 0.400 ;
    END
  END SS4BEG[12]
  PIN SS4BEG[13]
    DIRECTION OUTPUT ;
    USE SIGNAL ;
    ANTENNADIFFAREA 2.724000 ;
    PORT
      LAYER Metal2 ;
        RECT 199.960 0.000 200.360 0.400 ;
    END
  END SS4BEG[13]
  PIN SS4BEG[14]
    DIRECTION OUTPUT ;
    USE SIGNAL ;
    ANTENNADIFFAREA 2.724000 ;
    PORT
      LAYER Metal2 ;
        RECT 201.880 0.000 202.280 0.400 ;
    END
  END SS4BEG[14]
  PIN SS4BEG[15]
    DIRECTION OUTPUT ;
    USE SIGNAL ;
    ANTENNADIFFAREA 2.724000 ;
    PORT
      LAYER Metal2 ;
        RECT 203.800 0.000 204.200 0.400 ;
    END
  END SS4BEG[15]
  PIN SS4BEG[1]
    DIRECTION OUTPUT ;
    USE SIGNAL ;
    ANTENNADIFFAREA 2.724000 ;
    PORT
      LAYER Metal2 ;
        RECT 176.920 0.000 177.320 0.400 ;
    END
  END SS4BEG[1]
  PIN SS4BEG[2]
    DIRECTION OUTPUT ;
    USE SIGNAL ;
    ANTENNADIFFAREA 2.724000 ;
    PORT
      LAYER Metal2 ;
        RECT 178.840 0.000 179.240 0.400 ;
    END
  END SS4BEG[2]
  PIN SS4BEG[3]
    DIRECTION OUTPUT ;
    USE SIGNAL ;
    ANTENNADIFFAREA 2.724000 ;
    PORT
      LAYER Metal2 ;
        RECT 180.760 0.000 181.160 0.400 ;
    END
  END SS4BEG[3]
  PIN SS4BEG[4]
    DIRECTION OUTPUT ;
    USE SIGNAL ;
    ANTENNADIFFAREA 2.724000 ;
    PORT
      LAYER Metal2 ;
        RECT 182.680 0.000 183.080 0.400 ;
    END
  END SS4BEG[4]
  PIN SS4BEG[5]
    DIRECTION OUTPUT ;
    USE SIGNAL ;
    ANTENNADIFFAREA 2.724000 ;
    PORT
      LAYER Metal2 ;
        RECT 184.600 0.000 185.000 0.400 ;
    END
  END SS4BEG[5]
  PIN SS4BEG[6]
    DIRECTION OUTPUT ;
    USE SIGNAL ;
    ANTENNADIFFAREA 2.724000 ;
    PORT
      LAYER Metal2 ;
        RECT 186.520 0.000 186.920 0.400 ;
    END
  END SS4BEG[6]
  PIN SS4BEG[7]
    DIRECTION OUTPUT ;
    USE SIGNAL ;
    ANTENNADIFFAREA 2.724000 ;
    PORT
      LAYER Metal2 ;
        RECT 188.440 0.000 188.840 0.400 ;
    END
  END SS4BEG[7]
  PIN SS4BEG[8]
    DIRECTION OUTPUT ;
    USE SIGNAL ;
    ANTENNADIFFAREA 2.724000 ;
    PORT
      LAYER Metal2 ;
        RECT 190.360 0.000 190.760 0.400 ;
    END
  END SS4BEG[8]
  PIN SS4BEG[9]
    DIRECTION OUTPUT ;
    USE SIGNAL ;
    ANTENNADIFFAREA 2.724000 ;
    PORT
      LAYER Metal2 ;
        RECT 192.280 0.000 192.680 0.400 ;
    END
  END SS4BEG[9]
  PIN SS4END[0]
    DIRECTION INPUT ;
    USE SIGNAL ;
    ANTENNAGATEAREA 1.120600 ;
    ANTENNADIFFAREA 20.153999 ;
    PORT
      LAYER Metal2 ;
        RECT 175.000 215.060 175.400 215.460 ;
    END
  END SS4END[0]
  PIN SS4END[10]
    DIRECTION INPUT ;
    USE SIGNAL ;
    ANTENNAGATEAREA 0.180700 ;
    ANTENNADIFFAREA 2.015400 ;
    PORT
      LAYER Metal2 ;
        RECT 194.200 215.060 194.600 215.460 ;
    END
  END SS4END[10]
  PIN SS4END[11]
    DIRECTION INPUT ;
    USE SIGNAL ;
    ANTENNAGATEAREA 0.180700 ;
    ANTENNADIFFAREA 2.015400 ;
    PORT
      LAYER Metal2 ;
        RECT 196.120 215.060 196.520 215.460 ;
    END
  END SS4END[11]
  PIN SS4END[12]
    DIRECTION INPUT ;
    USE SIGNAL ;
    ANTENNAGATEAREA 0.180700 ;
    ANTENNADIFFAREA 2.015400 ;
    PORT
      LAYER Metal2 ;
        RECT 198.040 215.060 198.440 215.460 ;
    END
  END SS4END[12]
  PIN SS4END[13]
    DIRECTION INPUT ;
    USE SIGNAL ;
    ANTENNAGATEAREA 0.180700 ;
    ANTENNADIFFAREA 2.015400 ;
    PORT
      LAYER Metal2 ;
        RECT 199.960 215.060 200.360 215.460 ;
    END
  END SS4END[13]
  PIN SS4END[14]
    DIRECTION INPUT ;
    USE SIGNAL ;
    ANTENNAGATEAREA 0.180700 ;
    PORT
      LAYER Metal2 ;
        RECT 201.880 215.060 202.280 215.460 ;
    END
  END SS4END[14]
  PIN SS4END[15]
    DIRECTION INPUT ;
    USE SIGNAL ;
    ANTENNAGATEAREA 0.180700 ;
    PORT
      LAYER Metal2 ;
        RECT 203.800 215.060 204.200 215.460 ;
    END
  END SS4END[15]
  PIN SS4END[1]
    DIRECTION INPUT ;
    USE SIGNAL ;
    ANTENNAGATEAREA 1.079000 ;
    PORT
      LAYER Metal2 ;
        RECT 176.920 215.060 177.320 215.460 ;
    END
  END SS4END[1]
  PIN SS4END[2]
    DIRECTION INPUT ;
    USE SIGNAL ;
    ANTENNAGATEAREA 1.092000 ;
    PORT
      LAYER Metal2 ;
        RECT 178.840 215.060 179.240 215.460 ;
    END
  END SS4END[2]
  PIN SS4END[3]
    DIRECTION INPUT ;
    USE SIGNAL ;
    ANTENNAGATEAREA 1.046500 ;
    PORT
      LAYER Metal2 ;
        RECT 180.760 215.060 181.160 215.460 ;
    END
  END SS4END[3]
  PIN SS4END[4]
    DIRECTION INPUT ;
    USE SIGNAL ;
    ANTENNAGATEAREA 0.180700 ;
    PORT
      LAYER Metal2 ;
        RECT 182.680 215.060 183.080 215.460 ;
    END
  END SS4END[4]
  PIN SS4END[5]
    DIRECTION INPUT ;
    USE SIGNAL ;
    ANTENNAGATEAREA 0.180700 ;
    ANTENNADIFFAREA 2.015400 ;
    PORT
      LAYER Metal2 ;
        RECT 184.600 215.060 185.000 215.460 ;
    END
  END SS4END[5]
  PIN SS4END[6]
    DIRECTION INPUT ;
    USE SIGNAL ;
    ANTENNAGATEAREA 0.180700 ;
    ANTENNADIFFAREA 2.015400 ;
    PORT
      LAYER Metal2 ;
        RECT 186.520 215.060 186.920 215.460 ;
    END
  END SS4END[6]
  PIN SS4END[7]
    DIRECTION INPUT ;
    USE SIGNAL ;
    ANTENNAGATEAREA 0.180700 ;
    ANTENNADIFFAREA 2.015400 ;
    PORT
      LAYER Metal2 ;
        RECT 188.440 215.060 188.840 215.460 ;
    END
  END SS4END[7]
  PIN SS4END[8]
    DIRECTION INPUT ;
    USE SIGNAL ;
    ANTENNAGATEAREA 0.180700 ;
    ANTENNADIFFAREA 2.015400 ;
    PORT
      LAYER Metal2 ;
        RECT 190.360 215.060 190.760 215.460 ;
    END
  END SS4END[8]
  PIN SS4END[9]
    DIRECTION INPUT ;
    USE SIGNAL ;
    ANTENNAGATEAREA 0.180700 ;
    ANTENNADIFFAREA 2.015400 ;
    PORT
      LAYER Metal2 ;
        RECT 192.280 215.060 192.680 215.460 ;
    END
  END SS4END[9]
  PIN UserCLK
    DIRECTION INPUT ;
    USE SIGNAL ;
    ANTENNAGATEAREA 1.450800 ;
    PORT
      LAYER Metal3 ;
        RECT 0.000 160.660 0.400 161.060 ;
    END
  END UserCLK
  PIN UserCLKo
    DIRECTION OUTPUT ;
    USE SIGNAL ;
    ANTENNADIFFAREA 2.724000 ;
    PORT
      LAYER Metal3 ;
        RECT 244.880 160.660 245.280 161.060 ;
    END
  END UserCLKo
  PIN VGND
    DIRECTION INOUT ;
    USE GROUND ;
    PORT
      LAYER Metal4 ;
        RECT 21.580 0.000 23.780 215.460 ;
    END
    PORT
      LAYER Metal4 ;
        RECT 97.180 0.000 99.380 215.460 ;
    END
    PORT
      LAYER Metal4 ;
        RECT 172.780 0.000 174.980 215.460 ;
    END
  END VGND
  PIN VPWR
    DIRECTION INOUT ;
    USE POWER ;
    PORT
      LAYER Metal4 ;
        RECT 15.380 0.000 17.580 215.460 ;
    END
    PORT
      LAYER Metal4 ;
        RECT 90.980 0.000 93.180 215.460 ;
    END
    PORT
      LAYER Metal4 ;
        RECT 166.580 0.000 168.780 215.460 ;
    END
  END VPWR
  PIN W1BEG[0]
    DIRECTION OUTPUT ;
    USE SIGNAL ;
    ANTENNADIFFAREA 2.724000 ;
    PORT
      LAYER Metal3 ;
        RECT 0.000 80.020 0.400 80.420 ;
    END
  END W1BEG[0]
  PIN W1BEG[1]
    DIRECTION OUTPUT ;
    USE SIGNAL ;
    ANTENNADIFFAREA 2.724000 ;
    PORT
      LAYER Metal3 ;
        RECT 0.000 81.700 0.400 82.100 ;
    END
  END W1BEG[1]
  PIN W1BEG[2]
    DIRECTION OUTPUT ;
    USE SIGNAL ;
    ANTENNADIFFAREA 2.724000 ;
    PORT
      LAYER Metal3 ;
        RECT 0.000 83.380 0.400 83.780 ;
    END
  END W1BEG[2]
  PIN W1BEG[3]
    DIRECTION OUTPUT ;
    USE SIGNAL ;
    ANTENNADIFFAREA 2.724000 ;
    PORT
      LAYER Metal3 ;
        RECT 0.000 85.060 0.400 85.460 ;
    END
  END W1BEG[3]
  PIN W1END[0]
    DIRECTION INPUT ;
    USE SIGNAL ;
    ANTENNAGATEAREA 1.999400 ;
    PORT
      LAYER Metal3 ;
        RECT 244.880 80.020 245.280 80.420 ;
    END
  END W1END[0]
  PIN W1END[1]
    DIRECTION INPUT ;
    USE SIGNAL ;
    ANTENNAGATEAREA 1.911000 ;
    PORT
      LAYER Metal3 ;
        RECT 244.880 81.700 245.280 82.100 ;
    END
  END W1END[1]
  PIN W1END[2]
    DIRECTION INPUT ;
    USE SIGNAL ;
    ANTENNAGATEAREA 2.354300 ;
    PORT
      LAYER Metal3 ;
        RECT 244.880 83.380 245.280 83.780 ;
    END
  END W1END[2]
  PIN W1END[3]
    DIRECTION INPUT ;
    USE SIGNAL ;
    ANTENNAGATEAREA 2.399800 ;
    PORT
      LAYER Metal3 ;
        RECT 244.880 85.060 245.280 85.460 ;
    END
  END W1END[3]
  PIN W2BEG[0]
    DIRECTION OUTPUT ;
    USE SIGNAL ;
    ANTENNADIFFAREA 2.724000 ;
    PORT
      LAYER Metal3 ;
        RECT 0.000 86.740 0.400 87.140 ;
    END
  END W2BEG[0]
  PIN W2BEG[1]
    DIRECTION OUTPUT ;
    USE SIGNAL ;
    ANTENNADIFFAREA 2.724000 ;
    PORT
      LAYER Metal3 ;
        RECT 0.000 88.420 0.400 88.820 ;
    END
  END W2BEG[1]
  PIN W2BEG[2]
    DIRECTION OUTPUT ;
    USE SIGNAL ;
    ANTENNADIFFAREA 2.724000 ;
    PORT
      LAYER Metal3 ;
        RECT 0.000 90.100 0.400 90.500 ;
    END
  END W2BEG[2]
  PIN W2BEG[3]
    DIRECTION OUTPUT ;
    USE SIGNAL ;
    ANTENNADIFFAREA 2.724000 ;
    PORT
      LAYER Metal3 ;
        RECT 0.000 91.780 0.400 92.180 ;
    END
  END W2BEG[3]
  PIN W2BEG[4]
    DIRECTION OUTPUT ;
    USE SIGNAL ;
    ANTENNADIFFAREA 2.724000 ;
    PORT
      LAYER Metal3 ;
        RECT 0.000 93.460 0.400 93.860 ;
    END
  END W2BEG[4]
  PIN W2BEG[5]
    DIRECTION OUTPUT ;
    USE SIGNAL ;
    ANTENNADIFFAREA 2.724000 ;
    PORT
      LAYER Metal3 ;
        RECT 0.000 95.140 0.400 95.540 ;
    END
  END W2BEG[5]
  PIN W2BEG[6]
    DIRECTION OUTPUT ;
    USE SIGNAL ;
    ANTENNADIFFAREA 2.724000 ;
    PORT
      LAYER Metal3 ;
        RECT 0.000 96.820 0.400 97.220 ;
    END
  END W2BEG[6]
  PIN W2BEG[7]
    DIRECTION OUTPUT ;
    USE SIGNAL ;
    ANTENNADIFFAREA 2.724000 ;
    PORT
      LAYER Metal3 ;
        RECT 0.000 98.500 0.400 98.900 ;
    END
  END W2BEG[7]
  PIN W2BEGb[0]
    DIRECTION OUTPUT ;
    USE SIGNAL ;
    ANTENNADIFFAREA 2.724000 ;
    PORT
      LAYER Metal3 ;
        RECT 0.000 100.180 0.400 100.580 ;
    END
  END W2BEGb[0]
  PIN W2BEGb[1]
    DIRECTION OUTPUT ;
    USE SIGNAL ;
    ANTENNADIFFAREA 2.724000 ;
    PORT
      LAYER Metal3 ;
        RECT 0.000 101.860 0.400 102.260 ;
    END
  END W2BEGb[1]
  PIN W2BEGb[2]
    DIRECTION OUTPUT ;
    USE SIGNAL ;
    ANTENNADIFFAREA 2.724000 ;
    PORT
      LAYER Metal3 ;
        RECT 0.000 103.540 0.400 103.940 ;
    END
  END W2BEGb[2]
  PIN W2BEGb[3]
    DIRECTION OUTPUT ;
    USE SIGNAL ;
    ANTENNADIFFAREA 2.724000 ;
    PORT
      LAYER Metal3 ;
        RECT 0.000 105.220 0.400 105.620 ;
    END
  END W2BEGb[3]
  PIN W2BEGb[4]
    DIRECTION OUTPUT ;
    USE SIGNAL ;
    ANTENNADIFFAREA 2.724000 ;
    PORT
      LAYER Metal3 ;
        RECT 0.000 106.900 0.400 107.300 ;
    END
  END W2BEGb[4]
  PIN W2BEGb[5]
    DIRECTION OUTPUT ;
    USE SIGNAL ;
    ANTENNADIFFAREA 2.724000 ;
    PORT
      LAYER Metal3 ;
        RECT 0.000 108.580 0.400 108.980 ;
    END
  END W2BEGb[5]
  PIN W2BEGb[6]
    DIRECTION OUTPUT ;
    USE SIGNAL ;
    ANTENNADIFFAREA 2.724000 ;
    PORT
      LAYER Metal3 ;
        RECT 0.000 110.260 0.400 110.660 ;
    END
  END W2BEGb[6]
  PIN W2BEGb[7]
    DIRECTION OUTPUT ;
    USE SIGNAL ;
    ANTENNADIFFAREA 2.724000 ;
    PORT
      LAYER Metal3 ;
        RECT 0.000 111.940 0.400 112.340 ;
    END
  END W2BEGb[7]
  PIN W2END[0]
    DIRECTION INPUT ;
    USE SIGNAL ;
    ANTENNAGATEAREA 0.426400 ;
    ANTENNADIFFAREA 8.061600 ;
    PORT
      LAYER Metal3 ;
        RECT 244.880 100.180 245.280 100.580 ;
    END
  END W2END[0]
  PIN W2END[1]
    DIRECTION INPUT ;
    USE SIGNAL ;
    ANTENNAGATEAREA 1.346800 ;
    PORT
      LAYER Metal3 ;
        RECT 244.880 101.860 245.280 102.260 ;
    END
  END W2END[1]
  PIN W2END[2]
    DIRECTION INPUT ;
    USE SIGNAL ;
    ANTENNAGATEAREA 0.938600 ;
    PORT
      LAYER Metal3 ;
        RECT 244.880 103.540 245.280 103.940 ;
    END
  END W2END[2]
  PIN W2END[3]
    DIRECTION INPUT ;
    USE SIGNAL ;
    ANTENNAGATEAREA 1.397000 ;
    PORT
      LAYER Metal3 ;
        RECT 244.880 105.220 245.280 105.620 ;
    END
  END W2END[3]
  PIN W2END[4]
    DIRECTION INPUT ;
    USE SIGNAL ;
    ANTENNAGATEAREA 1.549600 ;
    PORT
      LAYER Metal3 ;
        RECT 244.880 106.900 245.280 107.300 ;
    END
  END W2END[4]
  PIN W2END[5]
    DIRECTION INPUT ;
    USE SIGNAL ;
    ANTENNAGATEAREA 0.426400 ;
    PORT
      LAYER Metal3 ;
        RECT 244.880 108.580 245.280 108.980 ;
    END
  END W2END[5]
  PIN W2END[6]
    DIRECTION INPUT ;
    USE SIGNAL ;
    ANTENNAGATEAREA 0.426400 ;
    PORT
      LAYER Metal3 ;
        RECT 244.880 110.260 245.280 110.660 ;
    END
  END W2END[6]
  PIN W2END[7]
    DIRECTION INPUT ;
    USE SIGNAL ;
    ANTENNAGATEAREA 0.639600 ;
    PORT
      LAYER Metal3 ;
        RECT 244.880 111.940 245.280 112.340 ;
    END
  END W2END[7]
  PIN W2MID[0]
    DIRECTION INPUT ;
    USE SIGNAL ;
    ANTENNAGATEAREA 0.951900 ;
    PORT
      LAYER Metal3 ;
        RECT 244.880 86.740 245.280 87.140 ;
    END
  END W2MID[0]
  PIN W2MID[1]
    DIRECTION INPUT ;
    USE SIGNAL ;
    ANTENNAGATEAREA 1.062100 ;
    PORT
      LAYER Metal3 ;
        RECT 244.880 88.420 245.280 88.820 ;
    END
  END W2MID[1]
  PIN W2MID[2]
    DIRECTION INPUT ;
    USE SIGNAL ;
    ANTENNAGATEAREA 0.848900 ;
    PORT
      LAYER Metal3 ;
        RECT 244.880 90.100 245.280 90.500 ;
    END
  END W2MID[2]
  PIN W2MID[3]
    DIRECTION INPUT ;
    USE SIGNAL ;
    ANTENNAGATEAREA 1.033500 ;
    ANTENNADIFFAREA 10.077000 ;
    PORT
      LAYER Metal3 ;
        RECT 244.880 91.780 245.280 92.180 ;
    END
  END W2MID[3]
  PIN W2MID[4]
    DIRECTION INPUT ;
    USE SIGNAL ;
    ANTENNAGATEAREA 0.787800 ;
    PORT
      LAYER Metal3 ;
        RECT 244.880 93.460 245.280 93.860 ;
    END
  END W2MID[4]
  PIN W2MID[5]
    DIRECTION INPUT ;
    USE SIGNAL ;
    ANTENNAGATEAREA 1.062100 ;
    PORT
      LAYER Metal3 ;
        RECT 244.880 95.140 245.280 95.540 ;
    END
  END W2MID[5]
  PIN W2MID[6]
    DIRECTION INPUT ;
    USE SIGNAL ;
    ANTENNAGATEAREA 0.820300 ;
    PORT
      LAYER Metal3 ;
        RECT 244.880 96.820 245.280 97.220 ;
    END
  END W2MID[6]
  PIN W2MID[7]
    DIRECTION INPUT ;
    USE SIGNAL ;
    ANTENNAGATEAREA 1.062100 ;
    ANTENNADIFFAREA 20.153999 ;
    PORT
      LAYER Metal3 ;
        RECT 244.880 98.500 245.280 98.900 ;
    END
  END W2MID[7]
  PIN W6BEG[0]
    DIRECTION OUTPUT ;
    USE SIGNAL ;
    ANTENNADIFFAREA 2.724000 ;
    PORT
      LAYER Metal3 ;
        RECT 0.000 140.500 0.400 140.900 ;
    END
  END W6BEG[0]
  PIN W6BEG[10]
    DIRECTION OUTPUT ;
    USE SIGNAL ;
    ANTENNADIFFAREA 2.724000 ;
    PORT
      LAYER Metal3 ;
        RECT 0.000 157.300 0.400 157.700 ;
    END
  END W6BEG[10]
  PIN W6BEG[11]
    DIRECTION OUTPUT ;
    USE SIGNAL ;
    ANTENNADIFFAREA 2.724000 ;
    PORT
      LAYER Metal3 ;
        RECT 0.000 158.980 0.400 159.380 ;
    END
  END W6BEG[11]
  PIN W6BEG[1]
    DIRECTION OUTPUT ;
    USE SIGNAL ;
    ANTENNADIFFAREA 2.724000 ;
    PORT
      LAYER Metal3 ;
        RECT 0.000 142.180 0.400 142.580 ;
    END
  END W6BEG[1]
  PIN W6BEG[2]
    DIRECTION OUTPUT ;
    USE SIGNAL ;
    ANTENNADIFFAREA 2.724000 ;
    PORT
      LAYER Metal3 ;
        RECT 0.000 143.860 0.400 144.260 ;
    END
  END W6BEG[2]
  PIN W6BEG[3]
    DIRECTION OUTPUT ;
    USE SIGNAL ;
    ANTENNADIFFAREA 2.724000 ;
    PORT
      LAYER Metal3 ;
        RECT 0.000 145.540 0.400 145.940 ;
    END
  END W6BEG[3]
  PIN W6BEG[4]
    DIRECTION OUTPUT ;
    USE SIGNAL ;
    ANTENNADIFFAREA 2.724000 ;
    PORT
      LAYER Metal3 ;
        RECT 0.000 147.220 0.400 147.620 ;
    END
  END W6BEG[4]
  PIN W6BEG[5]
    DIRECTION OUTPUT ;
    USE SIGNAL ;
    ANTENNADIFFAREA 2.724000 ;
    PORT
      LAYER Metal3 ;
        RECT 0.000 148.900 0.400 149.300 ;
    END
  END W6BEG[5]
  PIN W6BEG[6]
    DIRECTION OUTPUT ;
    USE SIGNAL ;
    ANTENNADIFFAREA 2.724000 ;
    PORT
      LAYER Metal3 ;
        RECT 0.000 150.580 0.400 150.980 ;
    END
  END W6BEG[6]
  PIN W6BEG[7]
    DIRECTION OUTPUT ;
    USE SIGNAL ;
    ANTENNADIFFAREA 2.724000 ;
    PORT
      LAYER Metal3 ;
        RECT 0.000 152.260 0.400 152.660 ;
    END
  END W6BEG[7]
  PIN W6BEG[8]
    DIRECTION OUTPUT ;
    USE SIGNAL ;
    ANTENNADIFFAREA 2.724000 ;
    PORT
      LAYER Metal3 ;
        RECT 0.000 153.940 0.400 154.340 ;
    END
  END W6BEG[8]
  PIN W6BEG[9]
    DIRECTION OUTPUT ;
    USE SIGNAL ;
    ANTENNADIFFAREA 2.724000 ;
    PORT
      LAYER Metal3 ;
        RECT 0.000 155.620 0.400 156.020 ;
    END
  END W6BEG[9]
  PIN W6END[0]
    DIRECTION INPUT ;
    USE SIGNAL ;
    ANTENNAGATEAREA 2.293200 ;
    PORT
      LAYER Metal3 ;
        RECT 244.880 140.500 245.280 140.900 ;
    END
  END W6END[0]
  PIN W6END[10]
    DIRECTION INPUT ;
    USE SIGNAL ;
    ANTENNAGATEAREA 0.180700 ;
    PORT
      LAYER Metal3 ;
        RECT 244.880 157.300 245.280 157.700 ;
    END
  END W6END[10]
  PIN W6END[11]
    DIRECTION INPUT ;
    USE SIGNAL ;
    ANTENNAGATEAREA 0.180700 ;
    PORT
      LAYER Metal3 ;
        RECT 244.880 158.980 245.280 159.380 ;
    END
  END W6END[11]
  PIN W6END[1]
    DIRECTION INPUT ;
    USE SIGNAL ;
    ANTENNAGATEAREA 2.341300 ;
    PORT
      LAYER Metal3 ;
        RECT 244.880 142.180 245.280 142.580 ;
    END
  END W6END[1]
  PIN W6END[2]
    DIRECTION INPUT ;
    USE SIGNAL ;
    ANTENNAGATEAREA 0.180700 ;
    PORT
      LAYER Metal3 ;
        RECT 244.880 143.860 245.280 144.260 ;
    END
  END W6END[2]
  PIN W6END[3]
    DIRECTION INPUT ;
    USE SIGNAL ;
    ANTENNAGATEAREA 0.180700 ;
    PORT
      LAYER Metal3 ;
        RECT 244.880 145.540 245.280 145.940 ;
    END
  END W6END[3]
  PIN W6END[4]
    DIRECTION INPUT ;
    USE SIGNAL ;
    ANTENNAGATEAREA 0.180700 ;
    PORT
      LAYER Metal3 ;
        RECT 244.880 147.220 245.280 147.620 ;
    END
  END W6END[4]
  PIN W6END[5]
    DIRECTION INPUT ;
    USE SIGNAL ;
    ANTENNAGATEAREA 0.180700 ;
    PORT
      LAYER Metal3 ;
        RECT 244.880 148.900 245.280 149.300 ;
    END
  END W6END[5]
  PIN W6END[6]
    DIRECTION INPUT ;
    USE SIGNAL ;
    ANTENNAGATEAREA 0.180700 ;
    PORT
      LAYER Metal3 ;
        RECT 244.880 150.580 245.280 150.980 ;
    END
  END W6END[6]
  PIN W6END[7]
    DIRECTION INPUT ;
    USE SIGNAL ;
    ANTENNAGATEAREA 0.180700 ;
    PORT
      LAYER Metal3 ;
        RECT 244.880 152.260 245.280 152.660 ;
    END
  END W6END[7]
  PIN W6END[8]
    DIRECTION INPUT ;
    USE SIGNAL ;
    ANTENNAGATEAREA 0.180700 ;
    PORT
      LAYER Metal3 ;
        RECT 244.880 153.940 245.280 154.340 ;
    END
  END W6END[8]
  PIN W6END[9]
    DIRECTION INPUT ;
    USE SIGNAL ;
    ANTENNAGATEAREA 0.180700 ;
    PORT
      LAYER Metal3 ;
        RECT 244.880 155.620 245.280 156.020 ;
    END
  END W6END[9]
  PIN WW4BEG[0]
    DIRECTION OUTPUT ;
    USE SIGNAL ;
    ANTENNADIFFAREA 2.724000 ;
    PORT
      LAYER Metal3 ;
        RECT 0.000 113.620 0.400 114.020 ;
    END
  END WW4BEG[0]
  PIN WW4BEG[10]
    DIRECTION OUTPUT ;
    USE SIGNAL ;
    ANTENNADIFFAREA 2.724000 ;
    PORT
      LAYER Metal3 ;
        RECT 0.000 130.420 0.400 130.820 ;
    END
  END WW4BEG[10]
  PIN WW4BEG[11]
    DIRECTION OUTPUT ;
    USE SIGNAL ;
    ANTENNADIFFAREA 2.724000 ;
    PORT
      LAYER Metal3 ;
        RECT 0.000 132.100 0.400 132.500 ;
    END
  END WW4BEG[11]
  PIN WW4BEG[12]
    DIRECTION OUTPUT ;
    USE SIGNAL ;
    ANTENNADIFFAREA 2.724000 ;
    PORT
      LAYER Metal3 ;
        RECT 0.000 133.780 0.400 134.180 ;
    END
  END WW4BEG[12]
  PIN WW4BEG[13]
    DIRECTION OUTPUT ;
    USE SIGNAL ;
    ANTENNADIFFAREA 2.724000 ;
    PORT
      LAYER Metal3 ;
        RECT 0.000 135.460 0.400 135.860 ;
    END
  END WW4BEG[13]
  PIN WW4BEG[14]
    DIRECTION OUTPUT ;
    USE SIGNAL ;
    ANTENNADIFFAREA 2.724000 ;
    PORT
      LAYER Metal3 ;
        RECT 0.000 137.140 0.400 137.540 ;
    END
  END WW4BEG[14]
  PIN WW4BEG[15]
    DIRECTION OUTPUT ;
    USE SIGNAL ;
    ANTENNADIFFAREA 2.724000 ;
    PORT
      LAYER Metal3 ;
        RECT 0.000 138.820 0.400 139.220 ;
    END
  END WW4BEG[15]
  PIN WW4BEG[1]
    DIRECTION OUTPUT ;
    USE SIGNAL ;
    ANTENNADIFFAREA 2.724000 ;
    PORT
      LAYER Metal3 ;
        RECT 0.000 115.300 0.400 115.700 ;
    END
  END WW4BEG[1]
  PIN WW4BEG[2]
    DIRECTION OUTPUT ;
    USE SIGNAL ;
    ANTENNADIFFAREA 2.724000 ;
    PORT
      LAYER Metal3 ;
        RECT 0.000 116.980 0.400 117.380 ;
    END
  END WW4BEG[2]
  PIN WW4BEG[3]
    DIRECTION OUTPUT ;
    USE SIGNAL ;
    ANTENNADIFFAREA 2.724000 ;
    PORT
      LAYER Metal3 ;
        RECT 0.000 118.660 0.400 119.060 ;
    END
  END WW4BEG[3]
  PIN WW4BEG[4]
    DIRECTION OUTPUT ;
    USE SIGNAL ;
    ANTENNADIFFAREA 2.724000 ;
    PORT
      LAYER Metal3 ;
        RECT 0.000 120.340 0.400 120.740 ;
    END
  END WW4BEG[4]
  PIN WW4BEG[5]
    DIRECTION OUTPUT ;
    USE SIGNAL ;
    ANTENNADIFFAREA 2.724000 ;
    PORT
      LAYER Metal3 ;
        RECT 0.000 122.020 0.400 122.420 ;
    END
  END WW4BEG[5]
  PIN WW4BEG[6]
    DIRECTION OUTPUT ;
    USE SIGNAL ;
    ANTENNADIFFAREA 2.724000 ;
    PORT
      LAYER Metal3 ;
        RECT 0.000 123.700 0.400 124.100 ;
    END
  END WW4BEG[6]
  PIN WW4BEG[7]
    DIRECTION OUTPUT ;
    USE SIGNAL ;
    ANTENNADIFFAREA 2.724000 ;
    PORT
      LAYER Metal3 ;
        RECT 0.000 125.380 0.400 125.780 ;
    END
  END WW4BEG[7]
  PIN WW4BEG[8]
    DIRECTION OUTPUT ;
    USE SIGNAL ;
    ANTENNADIFFAREA 2.724000 ;
    PORT
      LAYER Metal3 ;
        RECT 0.000 127.060 0.400 127.460 ;
    END
  END WW4BEG[8]
  PIN WW4BEG[9]
    DIRECTION OUTPUT ;
    USE SIGNAL ;
    ANTENNADIFFAREA 2.724000 ;
    PORT
      LAYER Metal3 ;
        RECT 0.000 128.740 0.400 129.140 ;
    END
  END WW4BEG[9]
  PIN WW4END[0]
    DIRECTION INPUT ;
    USE SIGNAL ;
    ANTENNAGATEAREA 0.865800 ;
    ANTENNADIFFAREA 32.246399 ;
    PORT
      LAYER Metal3 ;
        RECT 244.880 113.620 245.280 114.020 ;
    END
  END WW4END[0]
  PIN WW4END[10]
    DIRECTION INPUT ;
    USE SIGNAL ;
    ANTENNAGATEAREA 0.180700 ;
    PORT
      LAYER Metal3 ;
        RECT 244.880 130.420 245.280 130.820 ;
    END
  END WW4END[10]
  PIN WW4END[11]
    DIRECTION INPUT ;
    USE SIGNAL ;
    ANTENNAGATEAREA 0.180700 ;
    PORT
      LAYER Metal3 ;
        RECT 244.880 132.100 245.280 132.500 ;
    END
  END WW4END[11]
  PIN WW4END[12]
    DIRECTION INPUT ;
    USE SIGNAL ;
    ANTENNAGATEAREA 0.180700 ;
    PORT
      LAYER Metal3 ;
        RECT 244.880 133.780 245.280 134.180 ;
    END
  END WW4END[12]
  PIN WW4END[13]
    DIRECTION INPUT ;
    USE SIGNAL ;
    ANTENNAGATEAREA 0.180700 ;
    PORT
      LAYER Metal3 ;
        RECT 244.880 135.460 245.280 135.860 ;
    END
  END WW4END[13]
  PIN WW4END[14]
    DIRECTION INPUT ;
    USE SIGNAL ;
    ANTENNAGATEAREA 0.180700 ;
    PORT
      LAYER Metal3 ;
        RECT 244.880 137.140 245.280 137.540 ;
    END
  END WW4END[14]
  PIN WW4END[15]
    DIRECTION INPUT ;
    USE SIGNAL ;
    ANTENNAGATEAREA 0.180700 ;
    PORT
      LAYER Metal3 ;
        RECT 244.880 138.820 245.280 139.220 ;
    END
  END WW4END[15]
  PIN WW4END[1]
    DIRECTION INPUT ;
    USE SIGNAL ;
    ANTENNAGATEAREA 0.886100 ;
    PORT
      LAYER Metal3 ;
        RECT 244.880 115.300 245.280 115.700 ;
    END
  END WW4END[1]
  PIN WW4END[2]
    DIRECTION INPUT ;
    USE SIGNAL ;
    ANTENNAGATEAREA 0.668200 ;
    PORT
      LAYER Metal3 ;
        RECT 244.880 116.980 245.280 117.380 ;
    END
  END WW4END[2]
  PIN WW4END[3]
    DIRECTION INPUT ;
    USE SIGNAL ;
    ANTENNAGATEAREA 0.878800 ;
    ANTENNADIFFAREA 8.061600 ;
    PORT
      LAYER Metal3 ;
        RECT 244.880 118.660 245.280 119.060 ;
    END
  END WW4END[3]
  PIN WW4END[4]
    DIRECTION INPUT ;
    USE SIGNAL ;
    ANTENNAGATEAREA 0.180700 ;
    PORT
      LAYER Metal3 ;
        RECT 244.880 120.340 245.280 120.740 ;
    END
  END WW4END[4]
  PIN WW4END[5]
    DIRECTION INPUT ;
    USE SIGNAL ;
    ANTENNAGATEAREA 0.180700 ;
    PORT
      LAYER Metal3 ;
        RECT 244.880 122.020 245.280 122.420 ;
    END
  END WW4END[5]
  PIN WW4END[6]
    DIRECTION INPUT ;
    USE SIGNAL ;
    ANTENNAGATEAREA 0.180700 ;
    PORT
      LAYER Metal3 ;
        RECT 244.880 123.700 245.280 124.100 ;
    END
  END WW4END[6]
  PIN WW4END[7]
    DIRECTION INPUT ;
    USE SIGNAL ;
    ANTENNAGATEAREA 0.180700 ;
    PORT
      LAYER Metal3 ;
        RECT 244.880 125.380 245.280 125.780 ;
    END
  END WW4END[7]
  PIN WW4END[8]
    DIRECTION INPUT ;
    USE SIGNAL ;
    ANTENNAGATEAREA 0.180700 ;
    PORT
      LAYER Metal3 ;
        RECT 244.880 127.060 245.280 127.460 ;
    END
  END WW4END[8]
  PIN WW4END[9]
    DIRECTION INPUT ;
    USE SIGNAL ;
    ANTENNAGATEAREA 0.180700 ;
    PORT
      LAYER Metal3 ;
        RECT 244.880 128.740 245.280 129.140 ;
    END
  END WW4END[9]
  OBS
      LAYER GatPoly ;
        RECT 2.880 3.630 242.400 211.830 ;
      LAYER Metal1 ;
        RECT 2.880 3.560 242.400 211.900 ;
      LAYER Metal2 ;
        RECT 0.375 214.850 1.030 215.185 ;
        RECT 1.850 214.850 2.950 215.185 ;
        RECT 3.770 214.850 4.870 215.185 ;
        RECT 5.690 214.850 6.790 215.185 ;
        RECT 7.610 214.850 8.710 215.185 ;
        RECT 9.530 214.850 10.630 215.185 ;
        RECT 11.450 214.850 12.550 215.185 ;
        RECT 13.370 214.850 14.470 215.185 ;
        RECT 15.290 214.850 16.390 215.185 ;
        RECT 17.210 214.850 18.310 215.185 ;
        RECT 19.130 214.850 20.230 215.185 ;
        RECT 21.050 214.850 22.150 215.185 ;
        RECT 22.970 214.850 24.070 215.185 ;
        RECT 24.890 214.850 25.990 215.185 ;
        RECT 26.810 214.850 27.910 215.185 ;
        RECT 28.730 214.850 29.830 215.185 ;
        RECT 30.650 214.850 31.750 215.185 ;
        RECT 32.570 214.850 33.670 215.185 ;
        RECT 34.490 214.850 35.590 215.185 ;
        RECT 36.410 214.850 37.510 215.185 ;
        RECT 38.330 214.850 40.390 215.185 ;
        RECT 41.210 214.850 42.310 215.185 ;
        RECT 43.130 214.850 44.230 215.185 ;
        RECT 45.050 214.850 46.150 215.185 ;
        RECT 46.970 214.850 48.070 215.185 ;
        RECT 48.890 214.850 49.990 215.185 ;
        RECT 50.810 214.850 51.910 215.185 ;
        RECT 52.730 214.850 53.830 215.185 ;
        RECT 54.650 214.850 55.750 215.185 ;
        RECT 56.570 214.850 57.670 215.185 ;
        RECT 58.490 214.850 59.590 215.185 ;
        RECT 60.410 214.850 61.510 215.185 ;
        RECT 62.330 214.850 63.430 215.185 ;
        RECT 64.250 214.850 65.350 215.185 ;
        RECT 66.170 214.850 67.270 215.185 ;
        RECT 68.090 214.850 69.190 215.185 ;
        RECT 70.010 214.850 72.070 215.185 ;
        RECT 72.890 214.850 73.990 215.185 ;
        RECT 74.810 214.850 75.910 215.185 ;
        RECT 76.730 214.850 77.830 215.185 ;
        RECT 78.650 214.850 79.750 215.185 ;
        RECT 80.570 214.850 81.670 215.185 ;
        RECT 82.490 214.850 83.590 215.185 ;
        RECT 84.410 214.850 85.510 215.185 ;
        RECT 86.330 214.850 87.430 215.185 ;
        RECT 88.250 214.850 89.350 215.185 ;
        RECT 90.170 214.850 91.270 215.185 ;
        RECT 92.090 214.850 93.190 215.185 ;
        RECT 94.010 214.850 95.110 215.185 ;
        RECT 95.930 214.850 97.030 215.185 ;
        RECT 97.850 214.850 98.950 215.185 ;
        RECT 99.770 214.850 100.870 215.185 ;
        RECT 101.690 214.850 102.790 215.185 ;
        RECT 103.610 214.850 104.710 215.185 ;
        RECT 105.530 214.850 106.630 215.185 ;
        RECT 107.450 214.850 108.550 215.185 ;
        RECT 109.370 214.850 111.430 215.185 ;
        RECT 112.250 214.850 113.350 215.185 ;
        RECT 114.170 214.850 115.270 215.185 ;
        RECT 116.090 214.850 117.190 215.185 ;
        RECT 118.010 214.850 119.110 215.185 ;
        RECT 119.930 214.850 121.030 215.185 ;
        RECT 121.850 214.850 122.950 215.185 ;
        RECT 123.770 214.850 124.870 215.185 ;
        RECT 125.690 214.850 126.790 215.185 ;
        RECT 127.610 214.850 128.710 215.185 ;
        RECT 129.530 214.850 130.630 215.185 ;
        RECT 131.450 214.850 132.550 215.185 ;
        RECT 133.370 214.850 134.470 215.185 ;
        RECT 135.290 214.850 136.390 215.185 ;
        RECT 137.210 214.850 138.310 215.185 ;
        RECT 139.130 214.850 140.230 215.185 ;
        RECT 141.050 214.850 143.110 215.185 ;
        RECT 143.930 214.850 145.030 215.185 ;
        RECT 145.850 214.850 146.950 215.185 ;
        RECT 147.770 214.850 148.870 215.185 ;
        RECT 149.690 214.850 150.790 215.185 ;
        RECT 151.610 214.850 152.710 215.185 ;
        RECT 153.530 214.850 154.630 215.185 ;
        RECT 155.450 214.850 156.550 215.185 ;
        RECT 157.370 214.850 158.470 215.185 ;
        RECT 159.290 214.850 160.390 215.185 ;
        RECT 161.210 214.850 162.310 215.185 ;
        RECT 163.130 214.850 164.230 215.185 ;
        RECT 165.050 214.850 166.150 215.185 ;
        RECT 166.970 214.850 168.070 215.185 ;
        RECT 168.890 214.850 169.990 215.185 ;
        RECT 170.810 214.850 171.910 215.185 ;
        RECT 172.730 214.850 174.790 215.185 ;
        RECT 175.610 214.850 176.710 215.185 ;
        RECT 177.530 214.850 178.630 215.185 ;
        RECT 179.450 214.850 180.550 215.185 ;
        RECT 181.370 214.850 182.470 215.185 ;
        RECT 183.290 214.850 184.390 215.185 ;
        RECT 185.210 214.850 186.310 215.185 ;
        RECT 187.130 214.850 188.230 215.185 ;
        RECT 189.050 214.850 190.150 215.185 ;
        RECT 190.970 214.850 192.070 215.185 ;
        RECT 192.890 214.850 193.990 215.185 ;
        RECT 194.810 214.850 195.910 215.185 ;
        RECT 196.730 214.850 197.830 215.185 ;
        RECT 198.650 214.850 199.750 215.185 ;
        RECT 200.570 214.850 201.670 215.185 ;
        RECT 202.490 214.850 203.590 215.185 ;
        RECT 204.410 214.850 206.470 215.185 ;
        RECT 207.290 214.850 208.390 215.185 ;
        RECT 209.210 214.850 210.310 215.185 ;
        RECT 211.130 214.850 212.230 215.185 ;
        RECT 213.050 214.850 214.150 215.185 ;
        RECT 214.970 214.850 216.070 215.185 ;
        RECT 216.890 214.850 217.990 215.185 ;
        RECT 218.810 214.850 219.910 215.185 ;
        RECT 220.730 214.850 221.830 215.185 ;
        RECT 222.650 214.850 223.750 215.185 ;
        RECT 224.570 214.850 225.670 215.185 ;
        RECT 226.490 214.850 227.590 215.185 ;
        RECT 228.410 214.850 229.510 215.185 ;
        RECT 230.330 214.850 231.430 215.185 ;
        RECT 232.250 214.850 233.350 215.185 ;
        RECT 234.170 214.850 235.270 215.185 ;
        RECT 236.090 214.850 237.190 215.185 ;
        RECT 238.010 214.850 239.110 215.185 ;
        RECT 239.930 214.850 241.030 215.185 ;
        RECT 241.850 214.850 242.950 215.185 ;
        RECT 243.770 214.850 244.905 215.185 ;
        RECT 0.375 0.610 244.905 214.850 ;
        RECT 0.375 0.275 1.030 0.610 ;
        RECT 1.850 0.275 2.950 0.610 ;
        RECT 3.770 0.275 4.870 0.610 ;
        RECT 5.690 0.275 6.790 0.610 ;
        RECT 7.610 0.275 8.710 0.610 ;
        RECT 9.530 0.275 10.630 0.610 ;
        RECT 11.450 0.275 12.550 0.610 ;
        RECT 13.370 0.275 14.470 0.610 ;
        RECT 15.290 0.275 16.390 0.610 ;
        RECT 17.210 0.275 18.310 0.610 ;
        RECT 19.130 0.275 20.230 0.610 ;
        RECT 21.050 0.275 22.150 0.610 ;
        RECT 22.970 0.275 24.070 0.610 ;
        RECT 24.890 0.275 25.990 0.610 ;
        RECT 26.810 0.275 27.910 0.610 ;
        RECT 28.730 0.275 29.830 0.610 ;
        RECT 30.650 0.275 31.750 0.610 ;
        RECT 32.570 0.275 33.670 0.610 ;
        RECT 34.490 0.275 35.590 0.610 ;
        RECT 36.410 0.275 37.510 0.610 ;
        RECT 38.330 0.275 40.390 0.610 ;
        RECT 41.210 0.275 42.310 0.610 ;
        RECT 43.130 0.275 44.230 0.610 ;
        RECT 45.050 0.275 46.150 0.610 ;
        RECT 46.970 0.275 48.070 0.610 ;
        RECT 48.890 0.275 49.990 0.610 ;
        RECT 50.810 0.275 51.910 0.610 ;
        RECT 52.730 0.275 53.830 0.610 ;
        RECT 54.650 0.275 55.750 0.610 ;
        RECT 56.570 0.275 57.670 0.610 ;
        RECT 58.490 0.275 59.590 0.610 ;
        RECT 60.410 0.275 61.510 0.610 ;
        RECT 62.330 0.275 63.430 0.610 ;
        RECT 64.250 0.275 65.350 0.610 ;
        RECT 66.170 0.275 67.270 0.610 ;
        RECT 68.090 0.275 69.190 0.610 ;
        RECT 70.010 0.275 72.070 0.610 ;
        RECT 72.890 0.275 73.990 0.610 ;
        RECT 74.810 0.275 75.910 0.610 ;
        RECT 76.730 0.275 77.830 0.610 ;
        RECT 78.650 0.275 79.750 0.610 ;
        RECT 80.570 0.275 81.670 0.610 ;
        RECT 82.490 0.275 83.590 0.610 ;
        RECT 84.410 0.275 85.510 0.610 ;
        RECT 86.330 0.275 87.430 0.610 ;
        RECT 88.250 0.275 89.350 0.610 ;
        RECT 90.170 0.275 91.270 0.610 ;
        RECT 92.090 0.275 93.190 0.610 ;
        RECT 94.010 0.275 95.110 0.610 ;
        RECT 95.930 0.275 97.030 0.610 ;
        RECT 97.850 0.275 98.950 0.610 ;
        RECT 99.770 0.275 100.870 0.610 ;
        RECT 101.690 0.275 102.790 0.610 ;
        RECT 103.610 0.275 104.710 0.610 ;
        RECT 105.530 0.275 106.630 0.610 ;
        RECT 107.450 0.275 108.550 0.610 ;
        RECT 109.370 0.275 111.430 0.610 ;
        RECT 112.250 0.275 113.350 0.610 ;
        RECT 114.170 0.275 115.270 0.610 ;
        RECT 116.090 0.275 117.190 0.610 ;
        RECT 118.010 0.275 119.110 0.610 ;
        RECT 119.930 0.275 121.030 0.610 ;
        RECT 121.850 0.275 122.950 0.610 ;
        RECT 123.770 0.275 124.870 0.610 ;
        RECT 125.690 0.275 126.790 0.610 ;
        RECT 127.610 0.275 128.710 0.610 ;
        RECT 129.530 0.275 130.630 0.610 ;
        RECT 131.450 0.275 132.550 0.610 ;
        RECT 133.370 0.275 134.470 0.610 ;
        RECT 135.290 0.275 136.390 0.610 ;
        RECT 137.210 0.275 138.310 0.610 ;
        RECT 139.130 0.275 140.230 0.610 ;
        RECT 141.050 0.275 143.110 0.610 ;
        RECT 143.930 0.275 145.030 0.610 ;
        RECT 145.850 0.275 146.950 0.610 ;
        RECT 147.770 0.275 148.870 0.610 ;
        RECT 149.690 0.275 150.790 0.610 ;
        RECT 151.610 0.275 152.710 0.610 ;
        RECT 153.530 0.275 154.630 0.610 ;
        RECT 155.450 0.275 156.550 0.610 ;
        RECT 157.370 0.275 158.470 0.610 ;
        RECT 159.290 0.275 160.390 0.610 ;
        RECT 161.210 0.275 162.310 0.610 ;
        RECT 163.130 0.275 164.230 0.610 ;
        RECT 165.050 0.275 166.150 0.610 ;
        RECT 166.970 0.275 168.070 0.610 ;
        RECT 168.890 0.275 169.990 0.610 ;
        RECT 170.810 0.275 171.910 0.610 ;
        RECT 172.730 0.275 174.790 0.610 ;
        RECT 175.610 0.275 176.710 0.610 ;
        RECT 177.530 0.275 178.630 0.610 ;
        RECT 179.450 0.275 180.550 0.610 ;
        RECT 181.370 0.275 182.470 0.610 ;
        RECT 183.290 0.275 184.390 0.610 ;
        RECT 185.210 0.275 186.310 0.610 ;
        RECT 187.130 0.275 188.230 0.610 ;
        RECT 189.050 0.275 190.150 0.610 ;
        RECT 190.970 0.275 192.070 0.610 ;
        RECT 192.890 0.275 193.990 0.610 ;
        RECT 194.810 0.275 195.910 0.610 ;
        RECT 196.730 0.275 197.830 0.610 ;
        RECT 198.650 0.275 199.750 0.610 ;
        RECT 200.570 0.275 201.670 0.610 ;
        RECT 202.490 0.275 203.590 0.610 ;
        RECT 204.410 0.275 206.470 0.610 ;
        RECT 207.290 0.275 208.390 0.610 ;
        RECT 209.210 0.275 210.310 0.610 ;
        RECT 211.130 0.275 212.230 0.610 ;
        RECT 213.050 0.275 214.150 0.610 ;
        RECT 214.970 0.275 216.070 0.610 ;
        RECT 216.890 0.275 217.990 0.610 ;
        RECT 218.810 0.275 219.910 0.610 ;
        RECT 220.730 0.275 221.830 0.610 ;
        RECT 222.650 0.275 223.750 0.610 ;
        RECT 224.570 0.275 225.670 0.610 ;
        RECT 226.490 0.275 227.590 0.610 ;
        RECT 228.410 0.275 229.510 0.610 ;
        RECT 230.330 0.275 231.430 0.610 ;
        RECT 232.250 0.275 233.350 0.610 ;
        RECT 234.170 0.275 235.270 0.610 ;
        RECT 236.090 0.275 237.190 0.610 ;
        RECT 238.010 0.275 239.110 0.610 ;
        RECT 239.930 0.275 241.030 0.610 ;
        RECT 241.850 0.275 242.950 0.610 ;
        RECT 243.770 0.275 244.905 0.610 ;
      LAYER Metal3 ;
        RECT 0.335 215.030 244.945 215.145 ;
        RECT 0.610 214.210 244.670 215.030 ;
        RECT 0.335 213.350 244.945 214.210 ;
        RECT 0.610 212.530 244.670 213.350 ;
        RECT 0.335 211.670 244.945 212.530 ;
        RECT 0.610 210.850 244.670 211.670 ;
        RECT 0.335 209.990 244.945 210.850 ;
        RECT 0.610 209.170 244.670 209.990 ;
        RECT 0.335 208.310 244.945 209.170 ;
        RECT 0.610 207.490 244.670 208.310 ;
        RECT 0.335 206.630 244.945 207.490 ;
        RECT 0.610 205.810 244.670 206.630 ;
        RECT 0.335 204.950 244.945 205.810 ;
        RECT 0.610 204.130 244.670 204.950 ;
        RECT 0.335 203.270 244.945 204.130 ;
        RECT 0.610 202.450 244.670 203.270 ;
        RECT 0.335 201.590 244.945 202.450 ;
        RECT 0.610 200.770 244.670 201.590 ;
        RECT 0.335 199.910 244.945 200.770 ;
        RECT 0.610 199.090 244.670 199.910 ;
        RECT 0.335 198.230 244.945 199.090 ;
        RECT 0.610 197.410 244.670 198.230 ;
        RECT 0.335 196.550 244.945 197.410 ;
        RECT 0.610 195.730 244.670 196.550 ;
        RECT 0.335 194.870 244.945 195.730 ;
        RECT 0.610 194.050 244.670 194.870 ;
        RECT 0.335 193.190 244.945 194.050 ;
        RECT 0.610 192.370 244.670 193.190 ;
        RECT 0.335 191.510 244.945 192.370 ;
        RECT 0.610 190.690 244.670 191.510 ;
        RECT 0.335 189.830 244.945 190.690 ;
        RECT 0.610 189.010 244.670 189.830 ;
        RECT 0.335 188.150 244.945 189.010 ;
        RECT 0.610 187.330 244.670 188.150 ;
        RECT 0.335 186.470 244.945 187.330 ;
        RECT 0.610 185.650 244.670 186.470 ;
        RECT 0.335 184.790 244.945 185.650 ;
        RECT 0.610 183.970 244.670 184.790 ;
        RECT 0.335 183.110 244.945 183.970 ;
        RECT 0.610 182.290 244.670 183.110 ;
        RECT 0.335 181.430 244.945 182.290 ;
        RECT 0.610 180.610 244.670 181.430 ;
        RECT 0.335 179.750 244.945 180.610 ;
        RECT 0.610 178.930 244.670 179.750 ;
        RECT 0.335 178.070 244.945 178.930 ;
        RECT 0.610 177.250 244.670 178.070 ;
        RECT 0.335 176.390 244.945 177.250 ;
        RECT 0.610 175.570 244.670 176.390 ;
        RECT 0.335 174.710 244.945 175.570 ;
        RECT 0.610 173.890 244.670 174.710 ;
        RECT 0.335 173.030 244.945 173.890 ;
        RECT 0.610 172.210 244.670 173.030 ;
        RECT 0.335 171.350 244.945 172.210 ;
        RECT 0.610 170.530 244.670 171.350 ;
        RECT 0.335 169.670 244.945 170.530 ;
        RECT 0.610 168.850 244.670 169.670 ;
        RECT 0.335 167.990 244.945 168.850 ;
        RECT 0.610 167.170 244.670 167.990 ;
        RECT 0.335 166.310 244.945 167.170 ;
        RECT 0.610 165.490 244.670 166.310 ;
        RECT 0.335 164.630 244.945 165.490 ;
        RECT 0.610 163.810 244.670 164.630 ;
        RECT 0.335 162.950 244.945 163.810 ;
        RECT 0.610 162.130 244.670 162.950 ;
        RECT 0.335 161.270 244.945 162.130 ;
        RECT 0.610 160.450 244.670 161.270 ;
        RECT 0.335 159.590 244.945 160.450 ;
        RECT 0.610 158.770 244.670 159.590 ;
        RECT 0.335 157.910 244.945 158.770 ;
        RECT 0.610 157.090 244.670 157.910 ;
        RECT 0.335 156.230 244.945 157.090 ;
        RECT 0.610 155.410 244.670 156.230 ;
        RECT 0.335 154.550 244.945 155.410 ;
        RECT 0.610 153.730 244.670 154.550 ;
        RECT 0.335 152.870 244.945 153.730 ;
        RECT 0.610 152.050 244.670 152.870 ;
        RECT 0.335 151.190 244.945 152.050 ;
        RECT 0.610 150.370 244.670 151.190 ;
        RECT 0.335 149.510 244.945 150.370 ;
        RECT 0.610 148.690 244.670 149.510 ;
        RECT 0.335 147.830 244.945 148.690 ;
        RECT 0.610 147.010 244.670 147.830 ;
        RECT 0.335 146.150 244.945 147.010 ;
        RECT 0.610 145.330 244.670 146.150 ;
        RECT 0.335 144.470 244.945 145.330 ;
        RECT 0.610 143.650 244.670 144.470 ;
        RECT 0.335 142.790 244.945 143.650 ;
        RECT 0.610 141.970 244.670 142.790 ;
        RECT 0.335 141.110 244.945 141.970 ;
        RECT 0.610 140.290 244.670 141.110 ;
        RECT 0.335 139.430 244.945 140.290 ;
        RECT 0.610 138.610 244.670 139.430 ;
        RECT 0.335 137.750 244.945 138.610 ;
        RECT 0.610 136.930 244.670 137.750 ;
        RECT 0.335 136.070 244.945 136.930 ;
        RECT 0.610 135.250 244.670 136.070 ;
        RECT 0.335 134.390 244.945 135.250 ;
        RECT 0.610 133.570 244.670 134.390 ;
        RECT 0.335 132.710 244.945 133.570 ;
        RECT 0.610 131.890 244.670 132.710 ;
        RECT 0.335 131.030 244.945 131.890 ;
        RECT 0.610 130.210 244.670 131.030 ;
        RECT 0.335 129.350 244.945 130.210 ;
        RECT 0.610 128.530 244.670 129.350 ;
        RECT 0.335 127.670 244.945 128.530 ;
        RECT 0.610 126.850 244.670 127.670 ;
        RECT 0.335 125.990 244.945 126.850 ;
        RECT 0.610 125.170 244.670 125.990 ;
        RECT 0.335 124.310 244.945 125.170 ;
        RECT 0.610 123.490 244.670 124.310 ;
        RECT 0.335 122.630 244.945 123.490 ;
        RECT 0.610 121.810 244.670 122.630 ;
        RECT 0.335 120.950 244.945 121.810 ;
        RECT 0.610 120.130 244.670 120.950 ;
        RECT 0.335 119.270 244.945 120.130 ;
        RECT 0.610 118.450 244.670 119.270 ;
        RECT 0.335 117.590 244.945 118.450 ;
        RECT 0.610 116.770 244.670 117.590 ;
        RECT 0.335 115.910 244.945 116.770 ;
        RECT 0.610 115.090 244.670 115.910 ;
        RECT 0.335 114.230 244.945 115.090 ;
        RECT 0.610 113.410 244.670 114.230 ;
        RECT 0.335 112.550 244.945 113.410 ;
        RECT 0.610 111.730 244.670 112.550 ;
        RECT 0.335 110.870 244.945 111.730 ;
        RECT 0.610 110.050 244.670 110.870 ;
        RECT 0.335 109.190 244.945 110.050 ;
        RECT 0.610 108.370 244.670 109.190 ;
        RECT 0.335 107.510 244.945 108.370 ;
        RECT 0.610 106.690 244.670 107.510 ;
        RECT 0.335 105.830 244.945 106.690 ;
        RECT 0.610 105.010 244.670 105.830 ;
        RECT 0.335 104.150 244.945 105.010 ;
        RECT 0.610 103.330 244.670 104.150 ;
        RECT 0.335 102.470 244.945 103.330 ;
        RECT 0.610 101.650 244.670 102.470 ;
        RECT 0.335 100.790 244.945 101.650 ;
        RECT 0.610 99.970 244.670 100.790 ;
        RECT 0.335 99.110 244.945 99.970 ;
        RECT 0.610 98.290 244.670 99.110 ;
        RECT 0.335 97.430 244.945 98.290 ;
        RECT 0.610 96.610 244.670 97.430 ;
        RECT 0.335 95.750 244.945 96.610 ;
        RECT 0.610 94.930 244.670 95.750 ;
        RECT 0.335 94.070 244.945 94.930 ;
        RECT 0.610 93.250 244.670 94.070 ;
        RECT 0.335 92.390 244.945 93.250 ;
        RECT 0.610 91.570 244.670 92.390 ;
        RECT 0.335 90.710 244.945 91.570 ;
        RECT 0.610 89.890 244.670 90.710 ;
        RECT 0.335 89.030 244.945 89.890 ;
        RECT 0.610 88.210 244.670 89.030 ;
        RECT 0.335 87.350 244.945 88.210 ;
        RECT 0.610 86.530 244.670 87.350 ;
        RECT 0.335 85.670 244.945 86.530 ;
        RECT 0.610 84.850 244.670 85.670 ;
        RECT 0.335 83.990 244.945 84.850 ;
        RECT 0.610 83.170 244.670 83.990 ;
        RECT 0.335 82.310 244.945 83.170 ;
        RECT 0.610 81.490 244.670 82.310 ;
        RECT 0.335 80.630 244.945 81.490 ;
        RECT 0.610 79.810 244.670 80.630 ;
        RECT 0.335 78.950 244.945 79.810 ;
        RECT 0.610 78.130 244.670 78.950 ;
        RECT 0.335 77.270 244.945 78.130 ;
        RECT 0.610 76.450 244.670 77.270 ;
        RECT 0.335 75.590 244.945 76.450 ;
        RECT 0.610 74.770 244.670 75.590 ;
        RECT 0.335 73.910 244.945 74.770 ;
        RECT 0.610 73.090 244.670 73.910 ;
        RECT 0.335 72.230 244.945 73.090 ;
        RECT 0.610 71.410 244.670 72.230 ;
        RECT 0.335 70.550 244.945 71.410 ;
        RECT 0.610 69.730 244.670 70.550 ;
        RECT 0.335 68.870 244.945 69.730 ;
        RECT 0.610 68.050 244.670 68.870 ;
        RECT 0.335 67.190 244.945 68.050 ;
        RECT 0.610 66.370 244.670 67.190 ;
        RECT 0.335 65.510 244.945 66.370 ;
        RECT 0.610 64.690 244.670 65.510 ;
        RECT 0.335 63.830 244.945 64.690 ;
        RECT 0.610 63.010 244.670 63.830 ;
        RECT 0.335 62.150 244.945 63.010 ;
        RECT 0.610 61.330 244.670 62.150 ;
        RECT 0.335 60.470 244.945 61.330 ;
        RECT 0.610 59.650 244.670 60.470 ;
        RECT 0.335 52.910 244.945 59.650 ;
        RECT 0.610 52.090 244.670 52.910 ;
        RECT 0.335 52.070 244.945 52.090 ;
        RECT 0.610 51.250 244.670 52.070 ;
        RECT 0.335 51.230 244.945 51.250 ;
        RECT 0.610 50.410 244.670 51.230 ;
        RECT 0.335 50.390 244.945 50.410 ;
        RECT 0.610 49.570 244.670 50.390 ;
        RECT 0.335 49.550 244.945 49.570 ;
        RECT 0.610 48.730 244.670 49.550 ;
        RECT 0.335 48.710 244.945 48.730 ;
        RECT 0.610 47.890 244.670 48.710 ;
        RECT 0.335 47.870 244.945 47.890 ;
        RECT 0.610 47.050 244.670 47.870 ;
        RECT 0.335 47.030 244.945 47.050 ;
        RECT 0.610 46.210 244.670 47.030 ;
        RECT 0.335 46.190 244.945 46.210 ;
        RECT 0.610 45.370 244.670 46.190 ;
        RECT 0.335 45.350 244.945 45.370 ;
        RECT 0.610 44.530 244.670 45.350 ;
        RECT 0.335 44.510 244.945 44.530 ;
        RECT 0.610 43.690 244.670 44.510 ;
        RECT 0.335 43.670 244.945 43.690 ;
        RECT 0.610 42.850 244.670 43.670 ;
        RECT 0.335 42.830 244.945 42.850 ;
        RECT 0.610 42.010 244.670 42.830 ;
        RECT 0.335 41.990 244.945 42.010 ;
        RECT 0.610 41.170 244.670 41.990 ;
        RECT 0.335 41.150 244.945 41.170 ;
        RECT 0.610 40.330 244.670 41.150 ;
        RECT 0.335 40.310 244.945 40.330 ;
        RECT 0.610 39.490 244.670 40.310 ;
        RECT 0.335 32.750 244.945 39.490 ;
        RECT 0.610 31.930 244.670 32.750 ;
        RECT 0.335 31.070 244.945 31.930 ;
        RECT 0.610 30.250 244.670 31.070 ;
        RECT 0.335 29.390 244.945 30.250 ;
        RECT 0.610 28.570 244.670 29.390 ;
        RECT 0.335 27.710 244.945 28.570 ;
        RECT 0.610 26.890 244.670 27.710 ;
        RECT 0.335 26.030 244.945 26.890 ;
        RECT 0.610 25.210 244.670 26.030 ;
        RECT 0.335 24.350 244.945 25.210 ;
        RECT 0.610 23.530 244.670 24.350 ;
        RECT 0.335 22.670 244.945 23.530 ;
        RECT 0.610 21.850 244.670 22.670 ;
        RECT 0.335 20.990 244.945 21.850 ;
        RECT 0.610 20.170 244.670 20.990 ;
        RECT 0.335 16.790 244.945 20.170 ;
        RECT 0.610 15.970 244.670 16.790 ;
        RECT 0.335 15.950 244.945 15.970 ;
        RECT 0.610 15.130 244.670 15.950 ;
        RECT 0.335 15.110 244.945 15.130 ;
        RECT 0.610 14.290 244.670 15.110 ;
        RECT 0.335 14.270 244.945 14.290 ;
        RECT 0.610 13.450 244.670 14.270 ;
        RECT 0.335 13.430 244.945 13.450 ;
        RECT 0.610 12.610 244.670 13.430 ;
        RECT 0.335 12.590 244.945 12.610 ;
        RECT 0.610 11.770 244.670 12.590 ;
        RECT 0.335 11.750 244.945 11.770 ;
        RECT 0.610 10.930 244.670 11.750 ;
        RECT 0.335 10.910 244.945 10.930 ;
        RECT 0.610 10.090 244.670 10.910 ;
        RECT 0.335 6.710 244.945 10.090 ;
        RECT 0.610 5.890 244.670 6.710 ;
        RECT 0.335 5.030 244.945 5.890 ;
        RECT 0.610 4.210 244.670 5.030 ;
        RECT 0.335 3.350 244.945 4.210 ;
        RECT 0.610 2.530 244.670 3.350 ;
        RECT 0.335 1.670 244.945 2.530 ;
        RECT 0.610 0.850 244.670 1.670 ;
        RECT 0.335 0.315 244.945 0.850 ;
      LAYER Metal4 ;
        RECT 0.380 0.275 15.170 215.185 ;
        RECT 17.790 0.275 21.370 215.185 ;
        RECT 23.990 0.275 90.770 215.185 ;
        RECT 93.390 0.275 96.970 215.185 ;
        RECT 99.590 0.275 166.370 215.185 ;
        RECT 168.990 0.275 172.570 215.185 ;
        RECT 175.190 0.275 244.900 215.185 ;
      LAYER TopMetal1 ;
        RECT 2.060 5.380 242.740 200.820 ;
  END
END RegFile
END LIBRARY

